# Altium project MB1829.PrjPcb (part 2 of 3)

## Sheet MCU_IO.SchDoc: MCU IOs
size A3; Date: Not used; ApprovedBy: Not used; CheckedBy: Not used; Author: Not used; CompanyName: STMicroelectronics; DrawnBy: Not used; Engineer: Not used; Organization: Not used; Address1: Not used; Address2: Not used; Address3: Not used; Address4: Not used; DocumentNumber: Not used; Revision: Not used; SheetNumber: 3; SheetTotal: 16

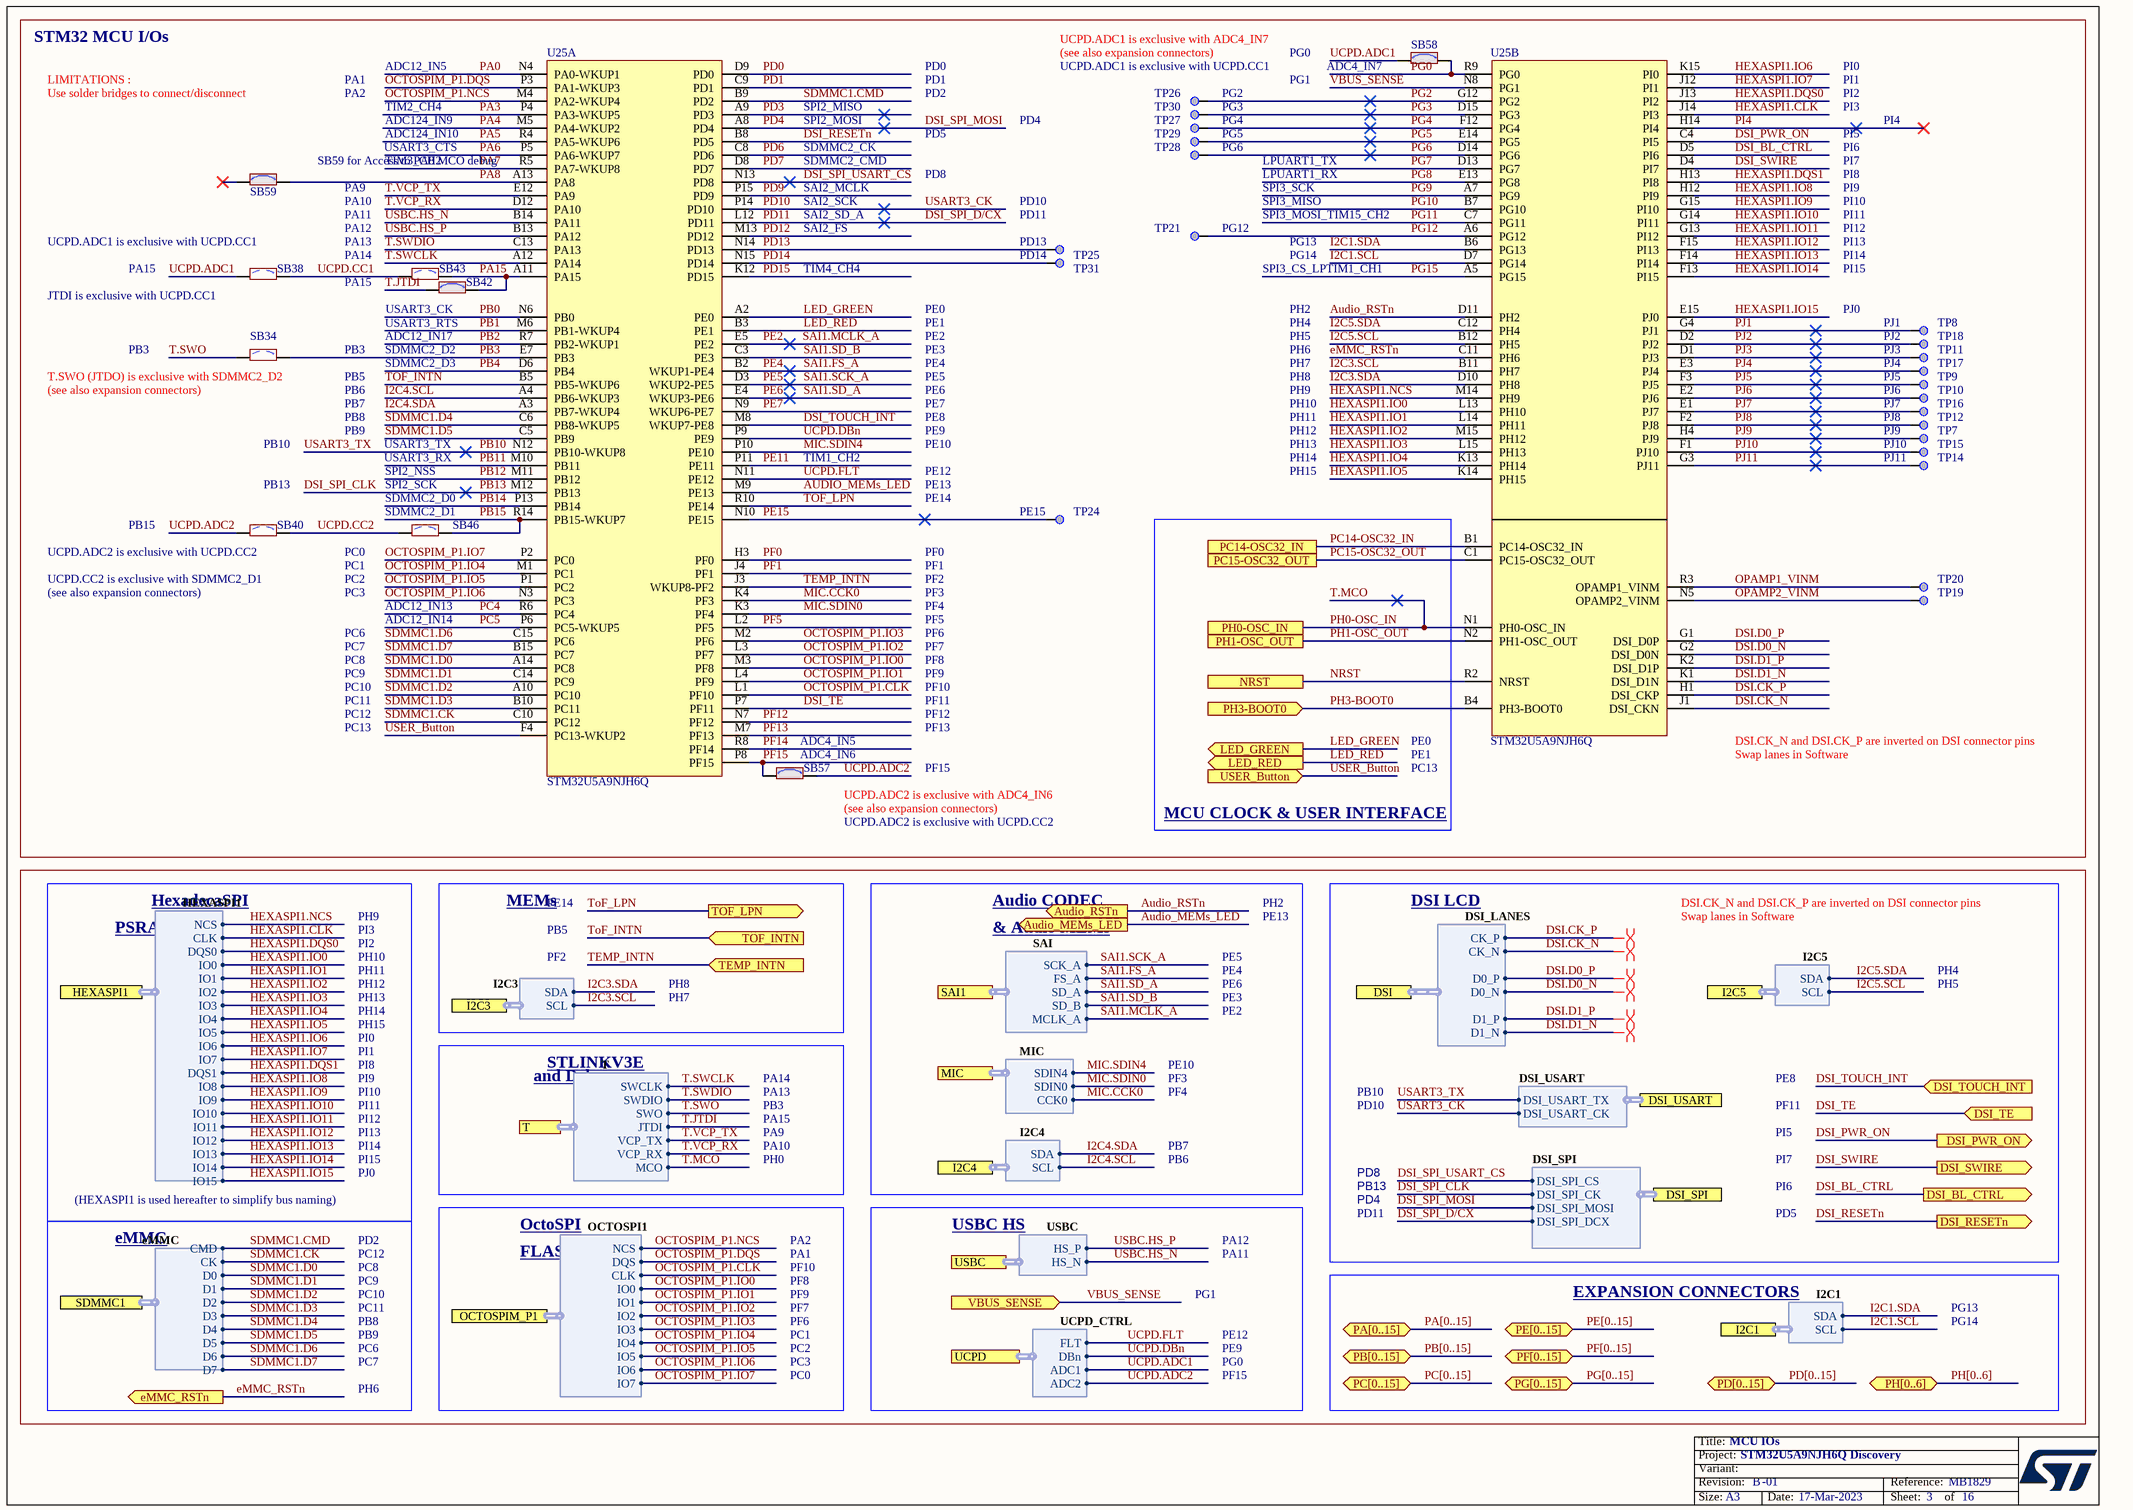
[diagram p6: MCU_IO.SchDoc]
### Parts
SB34  SB_OFF  [SOLDER-BRIDGE_R0402-0R]  (value not drawn)
SB38  SB_OFF  [SOLDER-BRIDGE_R0402-0R]  (value not drawn)
SB40  SB_OFF  [SOLDER-BRIDGE_R0402-0R]  (value not drawn)
SB42  SB_ON  [SOLDER-BRIDGE_R0402-0R]  (value not drawn)
SB43  SB_OFF  [SOLDER-BRIDGE_R0402-0R]  (value not drawn)
SB46  SB_OFF  [SOLDER-BRIDGE_R0402-0R]  (value not drawn)
SB57  SB_ON  [SOLDER-BRIDGE_R0402-0R]  (value not drawn)
SB58  SB_ON  [SOLDER-BRIDGE_R0402-0R]  (value not drawn)
SB59  SB_ON  [SOLDER-BRIDGE_R0402-0R]  (value not drawn)
TP7  Test Point  [TP_SMD_1MM]  (value not drawn)  (no BOM)
TP8  Test Point  [TP_SMD_1MM]  (value not drawn)  (no BOM)
TP9  Test Point  [TP_SMD_1MM]  (value not drawn)  (no BOM)
TP10  Test Point  [TP_SMD_1MM]  (value not drawn)  (no BOM)
TP11  Test Point  [TP_SMD_1MM]  (value not drawn)  (no BOM)
TP12  Test Point  [TP_SMD_1MM]  (value not drawn)  (no BOM)
TP14  Test Point  [TP_SMD_1MM]  (value not drawn)  (no BOM)
TP15  Test Point  [TP_SMD_1MM]  (value not drawn)  (no BOM)
TP16  Test Point  [TP_SMD_1MM]  (value not drawn)  (no BOM)
TP17  Test Point  [TP_SMD_1MM]  (value not drawn)  (no BOM)
TP18  Test Point  [TP_SMD_1MM]  (value not drawn)  (no BOM)
TP19  Test Point  [TP_SMD_1MM]  (value not drawn)  (no BOM)
TP20  Test Point  [TP_SMD_1MM]  (value not drawn)  (no BOM)
TP21  Test Point  [TP_SMD_1MM]  (value not drawn)  (no BOM)
TP24  Test Point  [TP_SMD_1MM]  (value not drawn)  (no BOM)
TP25  Test Point  [TP_SMD_1MM]  (value not drawn)  (no BOM)
TP26  Test Point  [TP_SMD_1MM]  (value not drawn)  (no BOM)
TP27  Test Point  [TP_SMD_1MM]  (value not drawn)  (no BOM)
TP28  Test Point  [TP_SMD_1MM]  (value not drawn)  (no BOM)
TP29  Test Point  [TP_SMD_1MM]  (value not drawn)  (no BOM)
TP30  Test Point  [TP_SMD_1MM]  (value not drawn)  (no BOM)
TP31  Test Point  [TP_SMD_1MM]  (value not drawn)  (no BOM)
U25  value STM32U5A9NJH6Q  [ICC_TFBGA216_13X13_P080_H1P10_CODE-A0L2]  (hidden comment: STM32U599NJH6Q_BGA216_SMPS)  (parts A,B of 3)

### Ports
Audio_MEMs_LED (out), Audio_RSTn (out), DSI (harness DSI_LANES), DSI_BL_CTRL (out), DSI_PWR_ON (out), DSI_RESETn (out), DSI_SPI (harness DSI_SPI), DSI_SWIRE (out), DSI_TE (in), DSI_TOUCH_INT (in), DSI_USART (harness DSI_USART), eMMC_RSTn (out), HEXASPI1 (harness HEXASPI1), I2C1 (harness I2C1), I2C3 (harness I2C3), I2C4 (harness I2C4), I2C5 (harness I2C5), LED_GREEN (out), LED_RED (out), MIC (harness MIC), NRST, OCTOSPIM_P1 (harness OCTOSPI1), PA[0..15] (bidir), PB[0..15] (bidir), PC14-OSC32_IN, PC15-OSC32_OUT, PC[0..15] (bidir), PD[0..15] (bidir), PE[0..15] (bidir), PF[0..15] (bidir), PG[0..15] (bidir), PH0-OSC_IN, PH1-OSC_OUT, PH3-BOOT0 (in), PH[0..6] (bidir), SAI1 (harness SAI), SDMMC1 (harness eMMC), T (harness T), TEMP_INTN (in), TOF_INTN (in), TOF_LPN (out), UCPD (harness UCPD_CTRL), USBC (harness USBC), USER_Button (in), VBUS_SENSE (in)

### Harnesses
T: SWCLK, SWDIO, SWO, JTDI, VCP_RX, VCP_TX, MCO
MIC: SDIN0, CCK0, SDIN4
OCTOSPI1: IO1, IO0, CLK, NCS, IO2, IO3, IO5, IO4, IO6, IO7, DQS
eMMC: D0, CMD, CK, D1, D2, D3, D4, D5, D6, D7
SAI: SD_B, FS_A, SD_A, SCK_A, MCLK_A
DSI_LANES: CK_P, CK_N, D0_P, D0_N, D1_N, D1_P
USBC: HS_P, HS_N
DSI_SPI: DSI_SPI_CS, DSI_SPI_MOSI, DSI_SPI_CK, DSI_SPI_DCX
DSI_USART: DSI_USART_CK, DSI_USART_TX
I2C4: SDA, SCL
I2C5: SDA, SCL
HEXASPI1: IO1, IO0, DQS0, NCS, IO2, IO3, IO5, IO4, IO6, IO7, CLK, DQS1, IO8, IO9, IO10, IO11, IO12, IO13, IO14, IO15
UCPD_CTRL: FLT, DBn, ADC1, ADC2
I2C1: SDA, SCL
I2C3: SDA, SCL

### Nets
AUDIO_MEMs_LED: U25.M9(PE13) ; port Audio_MEMs_LED
Audio_RSTn: U25.D11(PH2) ; port Audio_RSTn
DSI.CK_N: U25.J1(DSI_CKN) ; port DSI.CK_N
DSI.CK_P: U25.H1(DSI_CKP) ; port DSI.CK_P
DSI.D0_N: U25.G2(DSI_D0N) ; port DSI.D0_N
DSI.D0_P: U25.G1(DSI_D0P) ; port DSI.D0_P
DSI.D1_N: U25.K1(DSI_D1N) ; port DSI.D1_N
DSI.D1_P: U25.K2(DSI_D1P) ; port DSI.D1_P
DSI_BL_CTRL: U25.D5(PI6) ; port DSI_BL_CTRL
DSI_PWR_ON: U25.C4(PI5) ; port DSI_PWR_ON
DSI_RESETn: U25.B8(PD5) ; port DSI_RESETn
DSI_SPI_CLK: U25.M12(PB13) ; port DSI_SPI.DSI_SPI_CK  [also labelled PB13]
DSI_SPI_D/CX: U25.L12(PD11) ; port DSI_SPI.DSI_SPI_DCX  [also labelled PD11]
DSI_SPI_MOSI: U25.A8(PD4) ; port DSI_SPI.DSI_SPI_MOSI  [also labelled PD4]
DSI_SPI_USART_CS: U25.N13(PD8) ; port DSI_SPI.DSI_SPI_CS
DSI_SWIRE: U25.D4(PI7) ; port DSI_SWIRE
DSI_TE: U25.P7(PF11) ; port DSI_TE
DSI_TOUCH_INT: U25.M8(WKUP7-PE8) ; port DSI_TOUCH_INT
eMMC_RSTn: U25.C11(PH6) ; port eMMC_RSTn
HEXASPI1.CLK: U25.J14(PI3) ; port HEXASPI1.CLK
HEXASPI1.DQS0: U25.J13(PI2) ; port HEXASPI1.DQS0
HEXASPI1.DQS1: U25.H13(PI8) ; port HEXASPI1.DQS1
HEXASPI1.IO0: U25.L13(PH10) ; port HEXASPI1.IO0
HEXASPI1.IO1: U25.L14(PH11) ; port HEXASPI1.IO1
HEXASPI1.IO2: U25.M15(PH12) ; port HEXASPI1.IO2
HEXASPI1.IO3: U25.L15(PH13) ; port HEXASPI1.IO3
HEXASPI1.IO4: U25.K13(PH14) ; port HEXASPI1.IO4
HEXASPI1.IO5: U25.K14(PH15) ; port HEXASPI1.IO5
HEXASPI1.IO6: U25.K15(PI0) ; port HEXASPI1.IO6
HEXASPI1.IO7: U25.J12(PI1) ; port HEXASPI1.IO7
HEXASPI1.IO8: U25.H12(PI9) ; port HEXASPI1.IO8
HEXASPI1.IO9: U25.G15(PI10) ; port HEXASPI1.IO9
HEXASPI1.IO10: U25.G14(PI11) ; port HEXASPI1.IO10
HEXASPI1.IO11: U25.G13(PI12) ; port HEXASPI1.IO11
HEXASPI1.IO12: U25.F15(PI13) ; port HEXASPI1.IO12
HEXASPI1.IO13: U25.F14(PI14) ; port HEXASPI1.IO13
HEXASPI1.IO14: U25.F13(PI15) ; port HEXASPI1.IO14
HEXASPI1.IO15: U25.E15(PJ0) ; port HEXASPI1.IO15
HEXASPI1.NCS: U25.M14(PH9) ; port HEXASPI1.NCS
I2C1.SCL: U25.D7(PG14) ; port I2C1.SCL
I2C1.SDA: U25.B6(PG13) ; port I2C1.SDA
I2C3.SCL: U25.B11(PH7) ; port I2C3.SCL
I2C3.SDA: U25.D10(PH8) ; port I2C3.SDA
I2C4.SCL: U25.A4(PB6-WKUP3) ; port I2C4.SCL
I2C4.SDA: U25.A3(PB7-WKUP4) ; port I2C4.SDA
I2C5.SCL: U25.B12(PH5) ; port I2C5.SCL
I2C5.SDA: U25.C12(PH4) ; port I2C5.SDA
LED_GREEN: U25.A2(PE0) ; port LED_GREEN
LED_RED: U25.B3(PE1) ; port LED_RED
MIC.CCK0: U25.K4(PF3) ; port MIC.CCK0
MIC.SDIN0: U25.K3(PF4) ; port MIC.SDIN0
MIC.SDIN4: U25.P10(PE10) ; port MIC.SDIN4
NRST: U25.R2(NRST) ; port NRST
OCTOSPIM_P1.CLK: U25.L1(PF10) ; port OCTOSPIM_P1.CLK
OCTOSPIM_P1.DQS: U25.P3(PA1-WKUP3) ; port OCTOSPIM_P1.DQS
OCTOSPIM_P1.IO0: U25.M3(PF8) ; port OCTOSPIM_P1.IO0
OCTOSPIM_P1.IO1: U25.L4(PF9) ; port OCTOSPIM_P1.IO1
OCTOSPIM_P1.IO2: U25.L3(PF7) ; port OCTOSPIM_P1.IO2
OCTOSPIM_P1.IO3: U25.M2(PF6) ; port OCTOSPIM_P1.IO3
OCTOSPIM_P1.IO4: U25.M1(PC1) ; port OCTOSPIM_P1.IO4
OCTOSPIM_P1.IO5: U25.P1(PC2) ; port OCTOSPIM_P1.IO5
OCTOSPIM_P1.IO6: U25.N3(PC3) ; port OCTOSPIM_P1.IO6
OCTOSPIM_P1.IO7: U25.P2(PC0) ; port OCTOSPIM_P1.IO7
OCTOSPIM_P1.NCS: U25.M4(PA2-WKUP4) ; port OCTOSPIM_P1.NCS
OPAMP1_VINM: TP20.1 U25.R3(OPAMP1_VINM)
OPAMP2_VINM: TP19.1 U25.N5(OPAMP2_VINM)
PA0: U25.N4(PA0-WKUP1)
PA3: U25.P4(PA3-WKUP5)
PA4: U25.M5(PA4-WKUP2)
PA5: U25.R4(PA5-WKUP6)
PA6: U25.P5(PA6-WKUP7)
PA7: U25.R5(PA7-WKUP8)
PA8: SB59.2 U25.A13(PA8)
PA15: SB42.2 SB43.2 U25.A11(PA15)
PB0: U25.N6(PB0)
PB1: U25.M6(PB1-WKUP4)
PB2: U25.R7(PB2-WKUP1)
PB3: SB34.2 U25.E7(PB3)
PB4: U25.D6(PB4)
PB10: U25.N12(PB10-WKUP8) ; port DSI_USART.DSI_USART_TX  [also labelled USART3_TX]
PB11: U25.M10(PB11)
PB12: U25.M11(PB12)
PB14: U25.P13(PB14)
PB15: SB46.2 U25.R14(PB15-WKUP7)
PC4: U25.R6(PC4)
PC5: U25.P6(PC5-WKUP5)
PC14-OSC32_IN: U25.B1(PC14-OSC32_IN) ; port PC14-OSC32_IN
PC15-OSC32_OUT: U25.C1(PC15-OSC32_OUT) ; port PC15-OSC32_OUT
PD0: U25.D9(PD0)
PD1: U25.C9(PD1)
PD3: U25.A9(PD3)
PD6: U25.C8(PD6)
PD7: U25.D8(PD7)
PD9: U25.P15(PD9)
PD10: U25.P14(PD10) ; port DSI_USART.DSI_USART_CK  [also labelled USART3_CK]
PD12: U25.M13(PD12)
PD13: TP25.1 U25.N14(PD13)
PD14: TP31.1 U25.N15(PD14)
PD15: U25.K12(PD15)
PE2: U25.E5(PE2) ; port SAI1.MCLK_A  [also labelled SAI1.MCLK_A]
PE4: U25.B2(WKUP1-PE4) ; port SAI1.FS_A  [also labelled SAI1.FS_A]
PE5: U25.D3(WKUP2-PE5) ; port SAI1.SCK_A  [also labelled SAI1.SCK_A]
PE6: U25.E4(WKUP3-PE6) ; port SAI1.SD_A  [also labelled SAI1.SD_A]
PE7: U25.N9(WKUP6-PE7)
PE11: U25.P11(PE11)
PE15: TP24.1 U25.N10(PE15)
PF0: U25.H3(PF0)
PF1: U25.J4(PF1)
PF5: U25.L2(PF5)
PF12: U25.N7(PF12)
PF13: U25.M7(PF13)
PF14: U25.R8(PF14)
PF15: SB57.1 U25.P8(PF15)
PG0: SB58.2 U25.R9(PG0)
PG2: TP26.1 U25.G12(PG2)
PG3: TP30.1 U25.D15(PG3)
PG4: TP27.1 U25.F12(PG4)
PG5: TP29.1 U25.E14(PG5)
PG6: TP28.1 U25.D14(PG6)
PG7: U25.D13(PG7)
PG8: U25.E13(PG8)
PG9: U25.A7(PG9)
PG10: U25.B7(PG10)
PG11: U25.C7(PG11)
PG12: TP21.1 U25.A6(PG12)
PG15: U25.A5(PG15)
PH0-OSC_IN: U25.N1(PH0-OSC_IN) ; port PH0-OSC_IN, port T.MCO  [also labelled T.MCO]
PH1-OSC_OUT: U25.N2(PH1-OSC_OUT) ; port PH1-OSC_OUT
PH3-BOOT0: U25.B4(PH3-BOOT0) ; port PH3-BOOT0
PI4: U25.H14(PI4)
PJ1: TP8.1 U25.G4(PJ1)
PJ2: TP18.1 U25.D2(PJ2)
PJ3: TP11.1 U25.D1(PJ3)
PJ4: TP17.1 U25.E3(PJ4)
PJ5: TP9.1 U25.F3(PJ5)
PJ6: TP10.1 U25.E2(PJ6)
PJ7: TP16.1 U25.E1(PJ7)
PJ8: TP12.1 U25.F2(PJ8)
PJ9: TP7.1 U25.H4(PJ9)
PJ10: TP15.1 U25.F1(PJ10)
PJ11: TP14.1 U25.G3(PJ11)
SAI1.SD_B: U25.C3(PE3) ; port SAI1.SD_B
SDMMC1.CK: U25.C10(PC12) ; port SDMMC1.CK
SDMMC1.CMD: U25.B9(PD2) ; port SDMMC1.CMD
SDMMC1.D0: U25.A14(PC8) ; port SDMMC1.D0
SDMMC1.D1: U25.C14(PC9) ; port SDMMC1.D1
SDMMC1.D2: U25.A10(PC10) ; port SDMMC1.D2
SDMMC1.D3: U25.B10(PC11) ; port SDMMC1.D3
SDMMC1.D4: U25.C6(PB8-WKUP5) ; port SDMMC1.D4
SDMMC1.D5: U25.C5(PB9) ; port SDMMC1.D5
SDMMC1.D6: U25.C15(PC6) ; port SDMMC1.D6
SDMMC1.D7: U25.B15(PC7) ; port SDMMC1.D7
T.JTDI: SB42.1 ; port T.JTDI
T.SWCLK: U25.A12(PA14) ; port T.SWCLK
T.SWDIO: U25.C13(PA13) ; port T.SWDIO
T.SWO: SB34.1 ; port T.SWO
T.VCP_RX: U25.D12(PA10) ; port T.VCP_RX
T.VCP_TX: U25.E12(PA9) ; port T.VCP_TX
TEMP_INTN: U25.J3(WKUP8-PF2) ; port TEMP_INTN
ToF_INTN: U25.B5(PB5-WKUP6) ; port TOF_INTN
ToF_LPN: U25.R10(PE14) ; port TOF_LPN
UCPD.ADC1: SB38.1 SB58.1 ; port UCPD.ADC1
UCPD.ADC2: SB40.1 SB57.2 ; port UCPD.ADC2
UCPD.CC1: SB38.2 SB43.1
UCPD.CC2: SB40.2 SB46.1
UCPD.DBn: U25.P9(PE9) ; port UCPD.DBn
UCPD.FLT: U25.N11(PE12) ; port UCPD.FLT
USBC.HS_N: U25.B14(PA11) ; port USBC.HS_N
USBC.HS_P: U25.B13(PA12) ; port USBC.HS_P
USER_Button: U25.F4(PC13-WKUP2) ; port USER_Button
VBUS_SENSE: U25.N8(PG1) ; port VBUS_SENSE

Not connected (* = marked no-connect by the designer): SB59 1*

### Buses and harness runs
bus PA[0..15] = port PA[0..15]
bus PB[0..15] = port PB[0..15]
bus PC[0..15] = port PC[0..15]
bus PD[0..15] = port PD[0..15]
bus PE[0..15] = port PE[0..15]
bus PF[0..15] = port PF[0..15]
bus PG[0..15] = port PG[0..15]
bus PH[0..6] = port PH[0..6]

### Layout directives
differential pair; rule Impedance Constraint [Min = 95.00    Max = 105.0    ]: DSI.CK_N, DSI.CK_P, DSI.D0_N, DSI.D0_P, DSI.D1_N, DSI.D1_P

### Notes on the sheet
- STM32 MCU I/Os
- UCPD.ADC1 is exclusive with ADC4_IN7
- Use solder bridges to connect/disconnect
- LIMITATIONS :
- PA1
- PA2
- TIM2_CH4
- ADC12_IN5
- SPI2_MISO
- PD2
- PD1
- PD0
- UCPD.ADC1 is exclusive with UCPD.CC1
- (see also expansion connectors)
- PG2
- PG3
- PG1
- PG0
- (near SB58) ADC4_IN7
- PI0
- PI1
- PI2
- PI3
- (near SB59) SB59 for Access to PA8 MCO debug
- ADC124_IN9
- ADC124_IN10
- TIM3_CH2
- USART3_CTS
- SDMMC2_CK
- SDMMC2_CMD
- SPI2_MOSI
- PD8
- PD5
- PD4
- PG4
- PG5
- PG6
- LPUART1_TX
- LPUART1_RX
- PI8
- PI6
- PI7
- PI5
- PI4
- (near SB38) UCPD.ADC1 is exclusive with UCPD.CC1
- PA13
- PA10
- PA9
- PA12
- PA11
- SAI2_MCLK
- SAI2_SCK
- SAI2_SD_A
- SAI2_FS
- PD10
- PD11
- PD13
- (near TP21) PG12
- SPI3_SCK
- SPI3_MISO
- SPI3_MOSI_TIM15_CH2
- PG13
- PI9
- PI10
- PI11
- PI12
- PI13
- (near SB38) JTDI is exclusive with UCPD.CC1
- PA15
- PA14
- (near SB42) USART3_CK
- TIM4_CH4
- PE0
- PD14
- SPI3_CS_LPTIM1_CH1
- PG14
- PH2
- PI14
- PI15
- PJ0
- (near SB34) T.SWO (JTDO) is exclusive with SDMMC2_D2
- PB3
- PB5
- SDMMC2_D2
- SDMMC2_D3
- ADC12_IN17
- USART3_RTS
- PE1
- PE2
- PE3
- PE4
- PE5
- PH4
- PH5
- PH6
- PH7
- PH8
- PJ1
- PJ2
- PJ3
- PJ4
- PJ5
- (near SB34) (see also expansion connectors)
- PB10
- PB8
- PB9
- PB6
- PB7
- USART3_TX
- PE6
- PE7
- PE8
- PE10
- PE9
- PH9
- PH11
- PH12
- PH13
- PH10
- PJ6
- PJ7
- PJ8
- PJ9
- PJ10
- (near SB40) PB13
- (near SB46) SDMMC2_D0
- (near SB46) SDMMC2_D1
- (near SB46) SPI2_SCK
- SPI2_NSS
- USART3_RX
- TIM1_CH2
- PE13
- PE14
- PE12
- (near TP24) PE15
- PH14
- PH15
- PJ11
- (near SB40) UCPD.CC2 is exclusive with SDMMC2_D1
- (near SB40) UCPD.ADC2 is exclusive with UCPD.CC2
- PB15
- PC0
- PC1
- PC2
- PF1
- PF0
- PF2
- PC6
- PC7
- PC3
- ADC12_IN14
- ADC12_IN13
- PF6
- PF7
- PF4
- PF3
- PF5
- PC9
- PC12
- PC8
- PC10
- PC11
- PF9
- PF8
- PF10
- PF12
- PF11
- PC13
- (near SB57) ADC4_IN5
- (near SB57) ADC4_IN6
- PF13
- PF15
- DSI.CK_N and DSI.CK_P are inverted on DSI connector pins
- Swap lanes in Software
- (near SB57) UCPD.ADC2 is exclusive with ADC4_IN6
- UCPD.ADC2 is exclusive with UCPD.CC2
- (near SB57) (see also expansion connectors)
- MCU CLOCK & USER INTERFACE
- HexadecaSPI
- MEMs
- Audio CODEC
- DSI LCD
- PSRAM
- & Audio MEMs
- and Debug
- STLINKV3E
- PH0
- PB13
- (HEXASPI1 is used hereafter to simplify bus naming)
- eMMC
- OctoSPI
- FLASH
- USBC HS
- EXPANSION CONNECTORS

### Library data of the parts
SB34 SB38 SB40 SB43 SB46 = MCD-02162: Solder Bridge 0402 OFF; Part_Type: Misc; Manufacturer_Part_Number: RC0402JR-070RL; Manufacturer: YAGEO; Part_Preference: Recommended; Order_Code_RS: 618-5804; Component_Country_Of_Origin: China
SB42 SB57-SB59 = MCD-01618: Solder Bridge 0402 ON; Part_Type: Misc; Manufacturer_Part_Number: RC0402JR-070RL; Manufacturer: YAGEO; Part_Preference: Recommended; Order_Code_RS: 618-5804; Component_Country_Of_Origin: China
TP7-TP12 TP14-TP21 TP24-TP31 = MCD-00074: Test Point 1mm; Part_Type: Misc; Part_Preference: Recommended
U25 = MCD-03270: MCU, ARM Cortex-M33, 4MB Flash, 2.5MB RAM, With Crypto; Part_Type: IC; Part_Preference: Recommended; Manufacturer: STMICROELECTRONICS; Component_Country_Of_Origin: Unknown; ShowFields: YES; ID: 5386

## Sheet MCU_PWR.SchDoc: MCU PWR
size A4; Date: Not used; ApprovedBy: Not used; CheckedBy: Not used; Author: Not used; CompanyName: STMicroelectronics; DrawnBy: Not used; Engineer: Not used; Organization: Not used; Address1: Not used; Address2: Not used; Address3: Not used; Address4: Not used; DocumentNumber: Not used; Revision: Not used; SheetNumber: 5; SheetTotal: 16

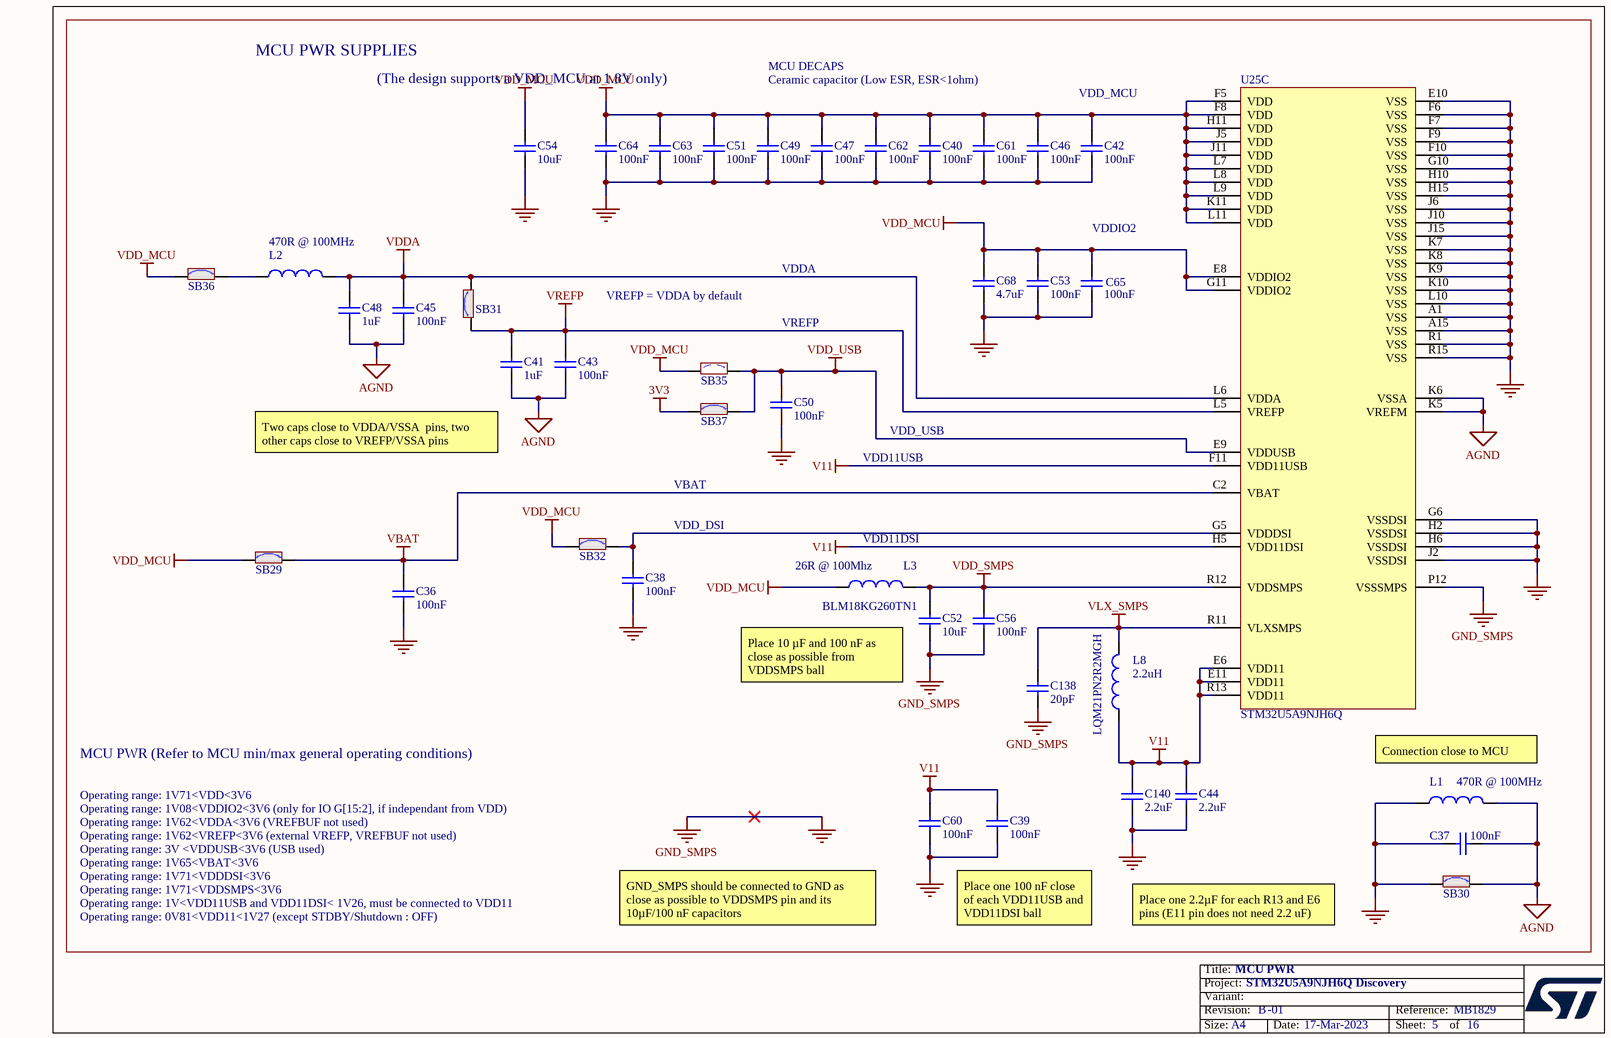
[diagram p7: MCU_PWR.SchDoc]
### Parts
C36  value 100nF  [C0402]  (hidden comment: Capacitor)
C37  value 100nF  [C0402]  (hidden comment: Capacitor)
C38  value 100nF  [C0402]  (hidden comment: Capacitor)
C39  value 100nF  [C0402]  (hidden comment: Capacitor)
C40  value 100nF  [C0402]  (hidden comment: Capacitor)
C41  value 1uF  [C0402]  (hidden comment: Capacitor)
C42  value 100nF  [C0402]  (hidden comment: Capacitor)
C43  value 100nF  [C0402]  (hidden comment: Capacitor)
C44  value 2.2uF  [C0402]  (hidden comment: Capacitor)
C45  value 100nF  [C0402]  (hidden comment: Capacitor)
C46  value 100nF  [C0402]  (hidden comment: Capacitor)
C47  value 100nF  [C0402]  (hidden comment: Capacitor)
C48  value 1uF  [C0402]  (hidden comment: Capacitor)
C49  value 100nF  [C0402]  (hidden comment: Capacitor)
C50  value 100nF  [C0402]  (hidden comment: Capacitor)
C51  value 100nF  [C0402]  (hidden comment: Capacitor)
C52  value 10uF  [C0603_H0P8]  (hidden comment: Capacitor)
C53  value 100nF  [C0402]  (hidden comment: Capacitor)
C54  value 10uF  [C0402]  (hidden comment: Capacitor)
C56  value 100nF  [C0402]  (hidden comment: Capacitor)
C60  value 100nF  [C0402]  (hidden comment: Capacitor)
C61  value 100nF  [C0402]  (hidden comment: Capacitor)
C62  value 100nF  [C0402]  (hidden comment: Capacitor)
C63  value 100nF  [C0402]  (hidden comment: Capacitor)
C64  value 100nF  [C0402]  (hidden comment: Capacitor)
C65  value 100nF  [C0402]  (hidden comment: Capacitor)
C68  value 4.7uF  [C0402]  (hidden comment: Capacitor)
C138  value 20pF  [C0402]  (hidden comment: Capacitor)
C140  value 2.2uF  [C0402]  (hidden comment: Capacitor)
L1  value 470R @ 100MHz  [IND_0402_MURATA_BLM15H_H0P5]  (hidden comment: Inductor)
L2  value 470R @ 100MHz  [IND_0402_MURATA_BLM15H_H0P5]  (hidden comment: Inductor)
L3  value 26R @ 100Mhz  Manufacturer_Part_Number: BLM18KG260TN1  [FIL_0603_H0P65]  (hidden comment: BEAD)
L8  value 2.2uH  Manufacturer_Part_Number: LQM21PN2R2MGH  [L0805_H0P9]  (hidden comment: Inductor)
SB29  SB_ON  [SOLDER-BRIDGE_R0402-0R]  (value not drawn)
SB30  SB_ON  [SOLDER-BRIDGE_R0402-0R]  (value not drawn)
SB31  SB_ON  [SOLDER-BRIDGE_R0402-0R]  (value not drawn)
SB32  SB_ON  [SOLDER-BRIDGE_R0402-0R]  (value not drawn)
SB35  SB_OFF  [SOLDER-BRIDGE_R0402-0R]  (value not drawn)
SB36  SB_ON  [SOLDER-BRIDGE_R0402-0R]  (value not drawn)
SB37  SB_ON  [SOLDER-BRIDGE_R0402-0R]  (value not drawn)
U25  value STM32U5A9NJH6Q  [ICC_TFBGA216_13X13_P080_H1P10_CODE-A0L2]  (hidden comment: STM32U599NJH6Q_BGA216_SMPS)  (part C of 3)

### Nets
3V3: SB37.1
AGND: C37.2 C41.1 C43.1 C45.1 C48.1 L1.2 SB30.2 U25.K5(VREFM) U25.K6(VSSA)
GND: C36.1 C37.1 C38.1 C39.1 C40.1 C42.1 C44.1 C46.1 C47.1 C49.1 C50.1 C51.1 C52.1 C53.1 C54.1 C56.1 C60.1 C61.1 C62.1 C63.1 C64.1 C65.1 C68.1 C138.1 C140.1 L1.1 SB30.1 U25.A1(VSS) U25.A15(VSS) U25.E10(VSS) U25.F6(VSS) U25.F7(VSS) U25.F9(VSS) U25.F10(VSS) U25.G6(VSSDSI) U25.G10(VSS) U25.H2(VSSDSI) U25.H6(VSSDSI) U25.H10(VSS) U25.H15(VSS) U25.J2(VSSDSI) U25.J6(VSS) U25.J10(VSS) U25.J15(VSS) U25.K7(VSS) U25.K8(VSS) U25.K9(VSS) U25.K10(VSS) U25.L10(VSS) U25.P12(VSSSMPS) U25.R1(VSS) U25.R15(VSS)  [also labelled GND_SMPS]
V11: C39.2 C44.2 C60.2 C140.2 L8.1 U25.E6(VDD11) U25.E11(VDD11) U25.F11(VDD11USB) U25.H5(VDD11DSI) U25.R13(VDD11)
VBAT: C36.2 SB29.2 U25.C2(VBAT)
VDD_MCU: C40.2 C42.2 C46.2 C47.2 C49.2 C51.2 C53.2 C54.2 C61.2 C62.2 C63.2 C64.2 C65.2 C68.2 L3.1 SB29.1 SB32.1 SB35.1 SB36.1 U25.E8(VDDIO2) U25.F5(VDD) U25.F8(VDD) U25.G11(VDDIO2) U25.H11(VDD) U25.J5(VDD) U25.J11(VDD) U25.K11(VDD) U25.L7(VDD) U25.L8(VDD) U25.L9(VDD) U25.L11(VDD)
VDD_SMPS: C52.2 C56.2 L3.2 U25.R12(VDDSMPS)
VDD_USB: C50.2 SB35.2 SB37.2 U25.E9(VDDUSB)
VDDA: C45.2 C48.2 L2.2 SB31.2 U25.L6(VDDA)
VLX_SMPS: C138.2 L8.2 U25.R11(VLXSMPS)
VREFP: C41.2 C43.2 SB31.1 U25.L5(VREFP)
NetC38_2: C38.2 SB32.2 U25.G5(VDDDSI)
NetL2_1: L2.1 SB36.2

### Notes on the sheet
- MCU PWR SUPPLIES
- (The design supports a VDD_MCU at 1.8V only)
- MCU DECAPS
- Ceramic capacitor (Low ESR, ESR<1ohm)
- VDD_MCU
- (near C65) VDDIO2
- VREFP = VDDA by default
- VDDA
- VREFP
- (near C41) Two caps close to VDDA/VSSA  pins, two other caps close to VREFP/VSSA pins
- VDD_USB
- VBAT
- VDD11USB
- VDD_DSI
- (near L3) VDD11DSI
- Place 10 µF and 100 nF as close as possible from VDDSMPS ball
- MCU PWR (Refer to MCU min/max general operating conditions)
- Connection close to MCU
- Operating range: 1V71<VDD<3V6
- Operating range: 1V08<VDDIO2<3V6 (only for IO G[15:2], if independant from VDD)
- Operating range: 1V62<VDDA<3V6 (VREFBUF not used)
- Operating range: 3V <VDDUSB<3V6 (USB used)
- Operating range: 1V62<VREFP<3V6 (external VREFP, VREFBUF not used)
- Operating range: 1V65<VBAT<3V6
- Operating range: 1V71<VDDSMPS<3V6
- Operating range: 1V71<VDDDSI<3V6
- Operating range: 1V<VDD11USB and VDD11DSI< 1V26, must be connected to VDD11
- Operating range: 0V81<VDD11<1V27 (except STDBY/Shutdown : OFF)
- GND_SMPS should be connected to GND as close as possible to VDDSMPS pin and its 10µF/100 nF capacitors
- Place one 100 nF close of each VDD11USB and VDD11DSI ball
- Place one 2.2µF for each R13 and E6 pins (E11 pin does not need 2.2 uF)

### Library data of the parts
C36-C40 C42 C43 C45-C47 C49-C51 C53 C56 C60-C65 = MCD-00006: Capacitor, MLCC, 100nF, 16V, X7R, +/-10%, 0402, T=0.5mm; Manufacturer_Part_Number: CC0402KRX7R7BB104; Manufacturer: YAGEO; Part_Preference: Recommended; Order_Code_RS: 616-9701; Component_Country_Of_Origin: China
C41 C48 = MCD-01722: Capacitor, MLCC, 1uF, 10V, X5R, +/-10%, 0402, T=0.5mm; Manufacturer_Part_Number: CC0402KRX5R6BB105; Manufacturer: YAGEO; Part_Preference: Recommended; Component_Country_Of_Origin: China
C44 C140 = MCD-02606: Capacitor, MLCC, 2.2uF, 6.3V, X5R, +/-10%, 0402, T=0.5mm; Part_Preference: Recommended; Manufacturer: YAGEO; Manufacturer_Part_Number: CC0402KRX5R5BB225; Order_Code_RS: 1992205
C52 = MCD-02605: Capacitor, MLCC, 10uF, 10V, X5R, +/-10%, 0603, T=0.8mm; Part_Preference: Recommended; Manufacturer: YAGEO; Manufacturer_Part_Number: CC0603KRX5R6BB106; Order_Code_RS: 2006536
C54 = MCD-01716: Capacitor, MLCC, 10uF, 6V3, X5R, +/-20%, 0402, T=0.5mm; Part_Preference: Recommended; Manufacturer: YAGEO; Manufacturer_Part_Number: CC0402MRX5R5BB106; Component_Country_Of_Origin: China
C68 = MCD-02608: Capacitor, MLCC, 4.7uF, 6.3V, X5R, +/-10%, 0402, T=0.5mm; Part_Preference: Recommended; Manufacturer: YAGEO; Manufacturer_Part_Number: CC0402KRX5R5BB475
C138 = MCD-00016: Capacitor, MLCC, 20pF, 50V, NPO, +/- 5%, 0402, T=0.5mm; Manufacturer: YAGEO; Manufacturer_Part_Number: CC0402JRNPO9BN200; Part_Preference: Recommended; Component_Country_Of_Origin: China
L1 L2 = MCD-01986: Ferrite bead, 470R @ 100MHz, +/-25%, 200mA, 0R6, 0402, T=0.55mm; Manufacturer_Part_Number: BLM15BD471SN1D; Manufacturer: MURATA; Part_Preference: Recommended; Order_Code_RS: 166-9836; Component_Country_Of_Origin: Japan
L3 = MCD-00305: Ferrite bead, 26R @ 100Mhz, +/-25%, 6000mA, 0R007, 0603, T=0.75mm; Part_Type: Inductor; Manufacturer: MURATA; Part_Preference: Recommended; Order_Code_RS: 747-4723; Component_Country_Of_Origin: Japan
L8 = MCD-01060: Inductor, 2.2uH, +/-20%, 0.7A, 0R156, 0805, T=0.9mm; Manufacturer: MURATA; Part_Preference: Recommended; Order_Code_RS: 166-9883; Component_Country_Of_Origin: Japan
SB29-SB32 SB36 SB37 = MCD-01618: as SB42 on sheet MCU_IO
SB35 = MCD-02162: as SB34 on sheet MCU_IO
U25 = MCD-03270: as U25 on sheet MCU_IO

## Sheet MECHANICAL.SchDoc: MECHANICAL
size A4; Date: Not used; ApprovedBy: Not used; CheckedBy: Not used; Author: Not used; CompanyName: STMicroelectronics; DrawnBy: Not used; Engineer: Not used; Organization: Not used; Address1: Not used; Address2: Not used; Address3: Not used; Address4: Not used; DocumentNumber: Not used; Revision: Not used; SheetNumber: 16; SheetTotal: 16

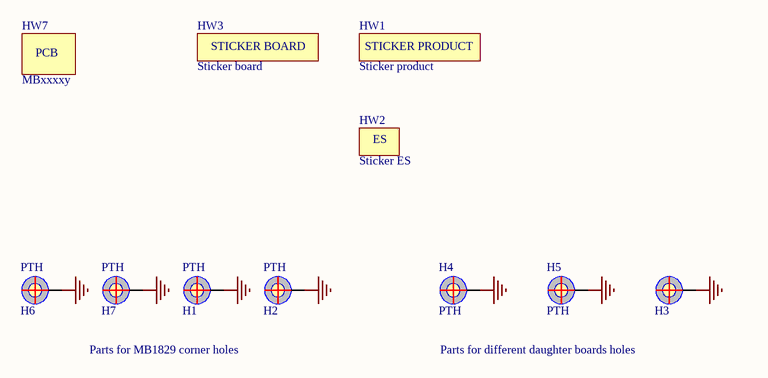
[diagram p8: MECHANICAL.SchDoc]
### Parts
H1  value PTH  [PTH_350_700_H-12]  (hidden comment: POSITION HOLE)  (no BOM)
H2  value PTH  [PTH_350_700_H-12]  (hidden comment: POSITION HOLE)  (no BOM)
H3  POSITION HOLE  [PTH_450_900]  (value not drawn)  (no BOM)
H4  value PTH  [PTH_350_500]  (hidden comment: POSITION HOLE)  (no BOM)
H5  value PTH  [PTH_350_500]  (hidden comment: POSITION HOLE)  (no BOM)
H6  value PTH  [PTH_350_700_H-12]  (hidden comment: POSITION HOLE)  (no BOM)
H7  value PTH  [PTH_350_700_H-12]  (hidden comment: POSITION HOLE)  (no BOM)
HW1  value Sticker product  [STICKER_PRODUCT_25X5]  (hidden comment: STICKER_PRODUCT)  (no BOM)
HW2  value Sticker ES  [STICKER_ES_6X6]  (hidden comment: STICKER_ES)  (no BOM)
HW3  value Sticker board  [STICKER_BOARD_25X9]  (hidden comment: STICKER_BOARD)  (no BOM)
HW7  value MBxxxxy  (hidden comment: PCB)  (no BOM)

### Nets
GND: H1.1 H2.1 H3.1 H4.1 H5.1 H6.1 H7.1

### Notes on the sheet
- Parts for MB1829 corner holes
- Parts for different daughter boards holes

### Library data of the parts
H1 H2 H6 H7 = MCD-02916: Position hole,  C7D3R5 with 12mm M3 pillar on bottom; Part_Type: Misc; Part_Preference: Recommended; ShowFields: YES; ID: 5032
H3 = MCD-01612: POSITION HOLE C9D4R5; Part_Type: Misc; Part_Preference: Recommended; ShowFields: YES; ID: 3712
H4 H5 = MCD-02915: Position Hole C5D3R5: with no pillar in 3D, with pad design = c500h350m510.; Part_Type: Misc; Part_Preference: Recommended; ShowFields: YES; ID: 5031
HW1 = MCD-02189: Sticker product 25x5 mm; Part_Preference: Recommended; Part_Type: Misc
HW2 = MCD-00234: Sticker ES 6x6 mm; Part_Type: Misc; Part_Preference: Recommended
HW3 = MCD-00235: Sticker Board 25x9 mm; Part_Preference: Recommended; Part_Type: Misc
HW7 = MCD-00216: PCB, xxxx for PCB number, Y for PCB revision; Part_Type: Misc; Part_Preference: Forbidden; ShowFields: YES; ID: 2653

## Sheet OCTOSPI_FLASH.SchDoc: OCTOSPI FLASH
size A4; Date: Not used; ApprovedBy: Not used; CheckedBy: Not used; Author: Not used; CompanyName: STMicroelectronics; DrawnBy: Not used; Engineer: Not used; Organization: Not used; Address1: Not used; Address2: Not used; Address3: Not used; Address4: Not used; DocumentNumber: Not used; Revision: Not used; SheetNumber: 6; SheetTotal: 16

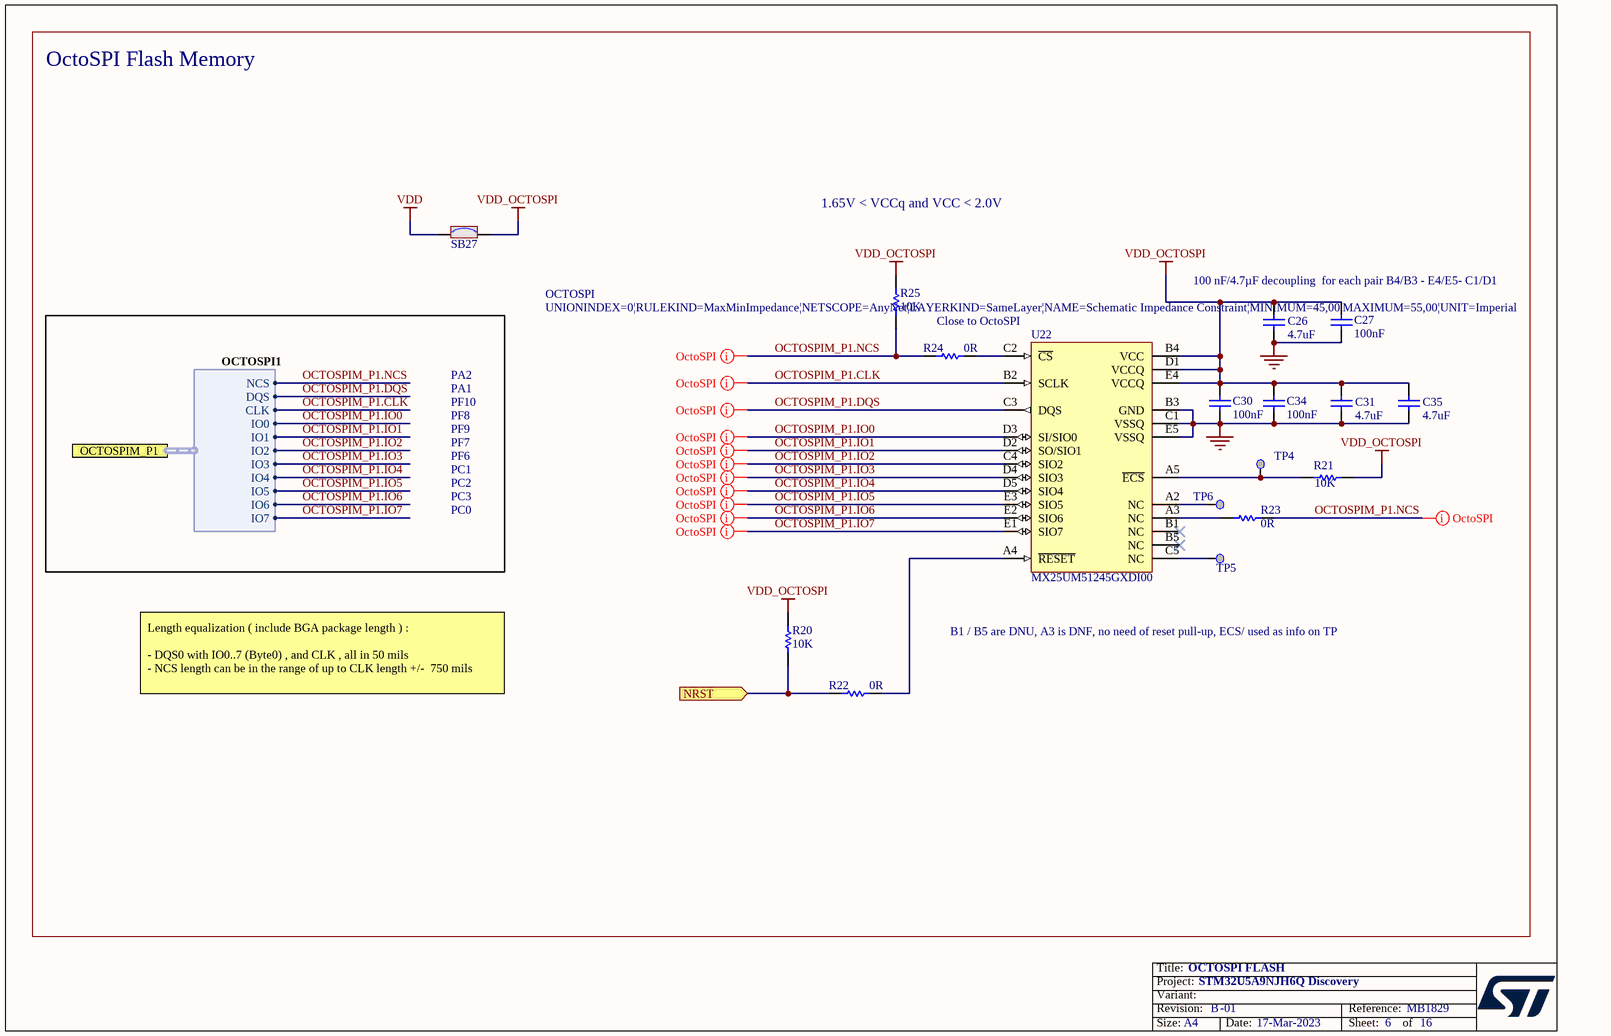
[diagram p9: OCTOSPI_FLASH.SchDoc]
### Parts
C26  value 4.7uF  [C0603]  (hidden comment: Capacitor)
C27  value 100nF  [C0402]  (hidden comment: Capacitor)
C30  value 100nF  [C0402]  (hidden comment: Capacitor)
C31  value 4.7uF  [C0603]  (hidden comment: Capacitor)
C34  value 100nF  [C0402]  (hidden comment: Capacitor)
C35  value 4.7uF  [C0603]  (hidden comment: Capacitor)
R20  value 10K  [R0402]  (hidden comment: Resistor)
R21  value 10K  [R0402]  (hidden comment: Resistor)
R22  value 0R  [R0402]  (hidden comment: Resistor)
R23  value 0R  [R0402]  (hidden comment: Resistor)
R24  value 0R  [R0402]  (hidden comment: Resistor)
R25  value 10K  [R0402]  (hidden comment: Resistor)
SB27  SB_ON  [SOLDER-BRIDGE_R0402-0R]  (value not drawn)
TP4  Test Point  [TP_SMD_1MM]  (value not drawn)  (no BOM)
TP5  Test Point  [TP_SMD_1MM]  (value not drawn)  (no BOM)
TP6  Test Point  [TP_SMD_1MM]  (value not drawn)  (no BOM)
U22  value MX25UM51245GXDI00  [ICC_BGA24_5X5-BALL-ARRAY_6X8_P1]  (hidden comment: MX25xx51245GXDx00)

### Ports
NRST (in), OCTOSPIM_P1 (harness OCTOSPI1)

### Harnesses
OCTOSPI1: IO1, IO0, CLK, NCS, IO2, IO3, IO5, IO4, IO6, IO7, DQS

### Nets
GND: C26.1 C27.1 C30.1 C31.1 C34.1 C35.1 U22.B3(GND) U22.C1(VSSQ) U22.E5(VSSQ)
VDD: SB27.1
VDD_OCTOSPI: C26.2 C27.2 C30.2 C31.2 C34.2 C35.2 R20.2 R21.2 R25.2 SB27.2 U22.B4(VCC) U22.D1(VCCQ) U22.E4(VCCQ)
NRST: R20.1 R22.1 ; port NRST
OCTOSPIM_P1.CLK: U22.B2(SCLK) ; port OCTOSPIM_P1.CLK
OCTOSPIM_P1.DQS: U22.C3(DQS) ; port OCTOSPIM_P1.DQS
OCTOSPIM_P1.IO0: U22.D3(SI/SIO0) ; port OCTOSPIM_P1.IO0
OCTOSPIM_P1.IO1: U22.D2(SO/SIO1) ; port OCTOSPIM_P1.IO1
OCTOSPIM_P1.IO2: U22.C4(SIO2) ; port OCTOSPIM_P1.IO2
OCTOSPIM_P1.IO3: U22.D4(SIO3) ; port OCTOSPIM_P1.IO3
OCTOSPIM_P1.IO4: U22.D5(SIO4) ; port OCTOSPIM_P1.IO4
OCTOSPIM_P1.IO5: U22.E3(SIO5) ; port OCTOSPIM_P1.IO5
OCTOSPIM_P1.IO6: U22.E2(SIO6) ; port OCTOSPIM_P1.IO6
OCTOSPIM_P1.IO7: U22.E1(SIO7) ; port OCTOSPIM_P1.IO7
OCTOSPIM_P1.NCS: R23.2 R24.1 R25.1 ; port OCTOSPIM_P1.NCS
NetR21_1: R21.1 TP4.1 U22.A5(~{ECS})
NetR22_2: R22.2 U22.A4(~{RESET})
NetR23_1: R23.1 U22.A3(NC)
NetR24_2: R24.2 U22.C2(~{CS})
NetTP5_1: TP5.1 U22.C5(NC)
NetTP6_1: TP6.1 U22.A2(NC)

Not connected (* = marked no-connect by the designer): U22 B1(NC)* B5(NC)*

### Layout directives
rule Matched Net Lengths [Tolerance = 1000mil]; net class OCTOSPI; rule Impedance Constraint [Min = 45.00    Max = 55.00    ]; rule Routing Layers [TopLayer - Enabled BottomLayer - Disabled]: OCTOSPIM_P1.NCS
rule Matched Net Lengths [Tolerance = 10mil]; net class OCTOSPI; rule Impedance Constraint [Min = 45.00    Max = 55.00    ]; rule Routing Layers [TopLayer - Enabled BottomLayer - Disabled]: OCTOSPIM_P1.CLK
rule Matched Net Lengths [Tolerance = 20mil]; net class OCTOSPI; rule Impedance Constraint [Min = 45.00    Max = 55.00    ]; rule Routing Layers [TopLayer - Enabled BottomLayer - Disabled]: OCTOSPIM_P1.DQS, OCTOSPIM_P1.IO0, OCTOSPIM_P1.IO1, OCTOSPIM_P1.IO2, OCTOSPIM_P1.IO3, OCTOSPIM_P1.IO4, OCTOSPIM_P1.IO5, OCTOSPIM_P1.IO6, OCTOSPIM_P1.IO7
rule Matched Net Lengths [Tolerance = 500mil]; net class OCTOSPI; rule Impedance Constraint [Min = 45.00    Max = 55.00    ]; rule Routing Layers [TopLayer - Enabled BottomLayer - Disabled]: OCTOSPIM_P1.NCS

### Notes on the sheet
- OctoSPI Flash Memory
- 1.65V < VCCq and VCC < 2.0V
- 100 nF/4.7µF decoupling  for each pair B4/B3 - E4/E5- C1/D1
- PA2
- Close to OctoSPI
- PF7
- PF9
- PF8
- PF10
- PA1
- PC0
- PC1
- PC3
- PC2
- PF6
- B1 / B5 are DNU, A3 is DNF, no need of reset pull-up, ECS/ used as info on TP
- Length equalization ( include BGA package length ) :
  - DQS0 with IO0..7 (Byte0) , and CLK , all in 50 mils
  - NCS length can be in the range of up to CLK length +/-  750 mils

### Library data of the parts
C26 C31 C35 = MCD-00009: Capacitor, MLCC, 4.7uF, 16V, X5R, +/-10%, 0603, T=0.8mm; Manufacturer_Part_Number: CC0603KRX5R7BB475; Manufacturer: YAGEO; Part_Preference: Recommended; Component_Country_Of_Origin: China
C27 C30 C34 = MCD-00006: as C36-C40 on sheet MCU_PWR
R20 R21 R25 = MCD-00053: Resistor, 10K, 0402, +/-1%, 1/16W; Manufacturer_Part_Number: RC0402FR-0710KL; Manufacturer: YAGEO; BMS_Part_Number: 9131590; Part_Preference: Recommended; Component_Country_Of_Origin: China
R22-R24 = MCD-00052: Resistor, 0R, 0402, +/-5%, 1/16W; Manufacturer_Part_Number: RC0402JR-070RL; Manufacturer: YAGEO; Part_Preference: Recommended; Order_Code_RS: 618-5804; Component_Country_Of_Origin: China
SB27 = MCD-01618: as SB42 on sheet MCU_IO
TP4-TP6 = MCD-00074: as TP7-TP12 on sheet MCU_IO
U22 = MCD-02166: Memory,Octo-SPI-NOR,512Mb,x1/x8,133/200MHz,1.8V,DTR,BGA24, CMOS MXSMIO; Part_Type: IC; Manufacturer: MACRONIX; Part_Preference: Recommended; Component_Country_Of_Origin: Unknown

## Sheet ST_LINK_V3E.SchDoc: ST_LINK_V3E
size A3; Date: Not used; ApprovedBy: Not used; CheckedBy: Not used; Author: Not used; CompanyName: STMicroelectronics; DrawnBy: Not used; Engineer: Not used; Organization: Not used; Address1: Not used; Address2: Not used; Address3: Not used; Address4: Not used; DocumentNumber: Not used; Revision: Not used; SheetNumber: 15; SheetTotal: 16

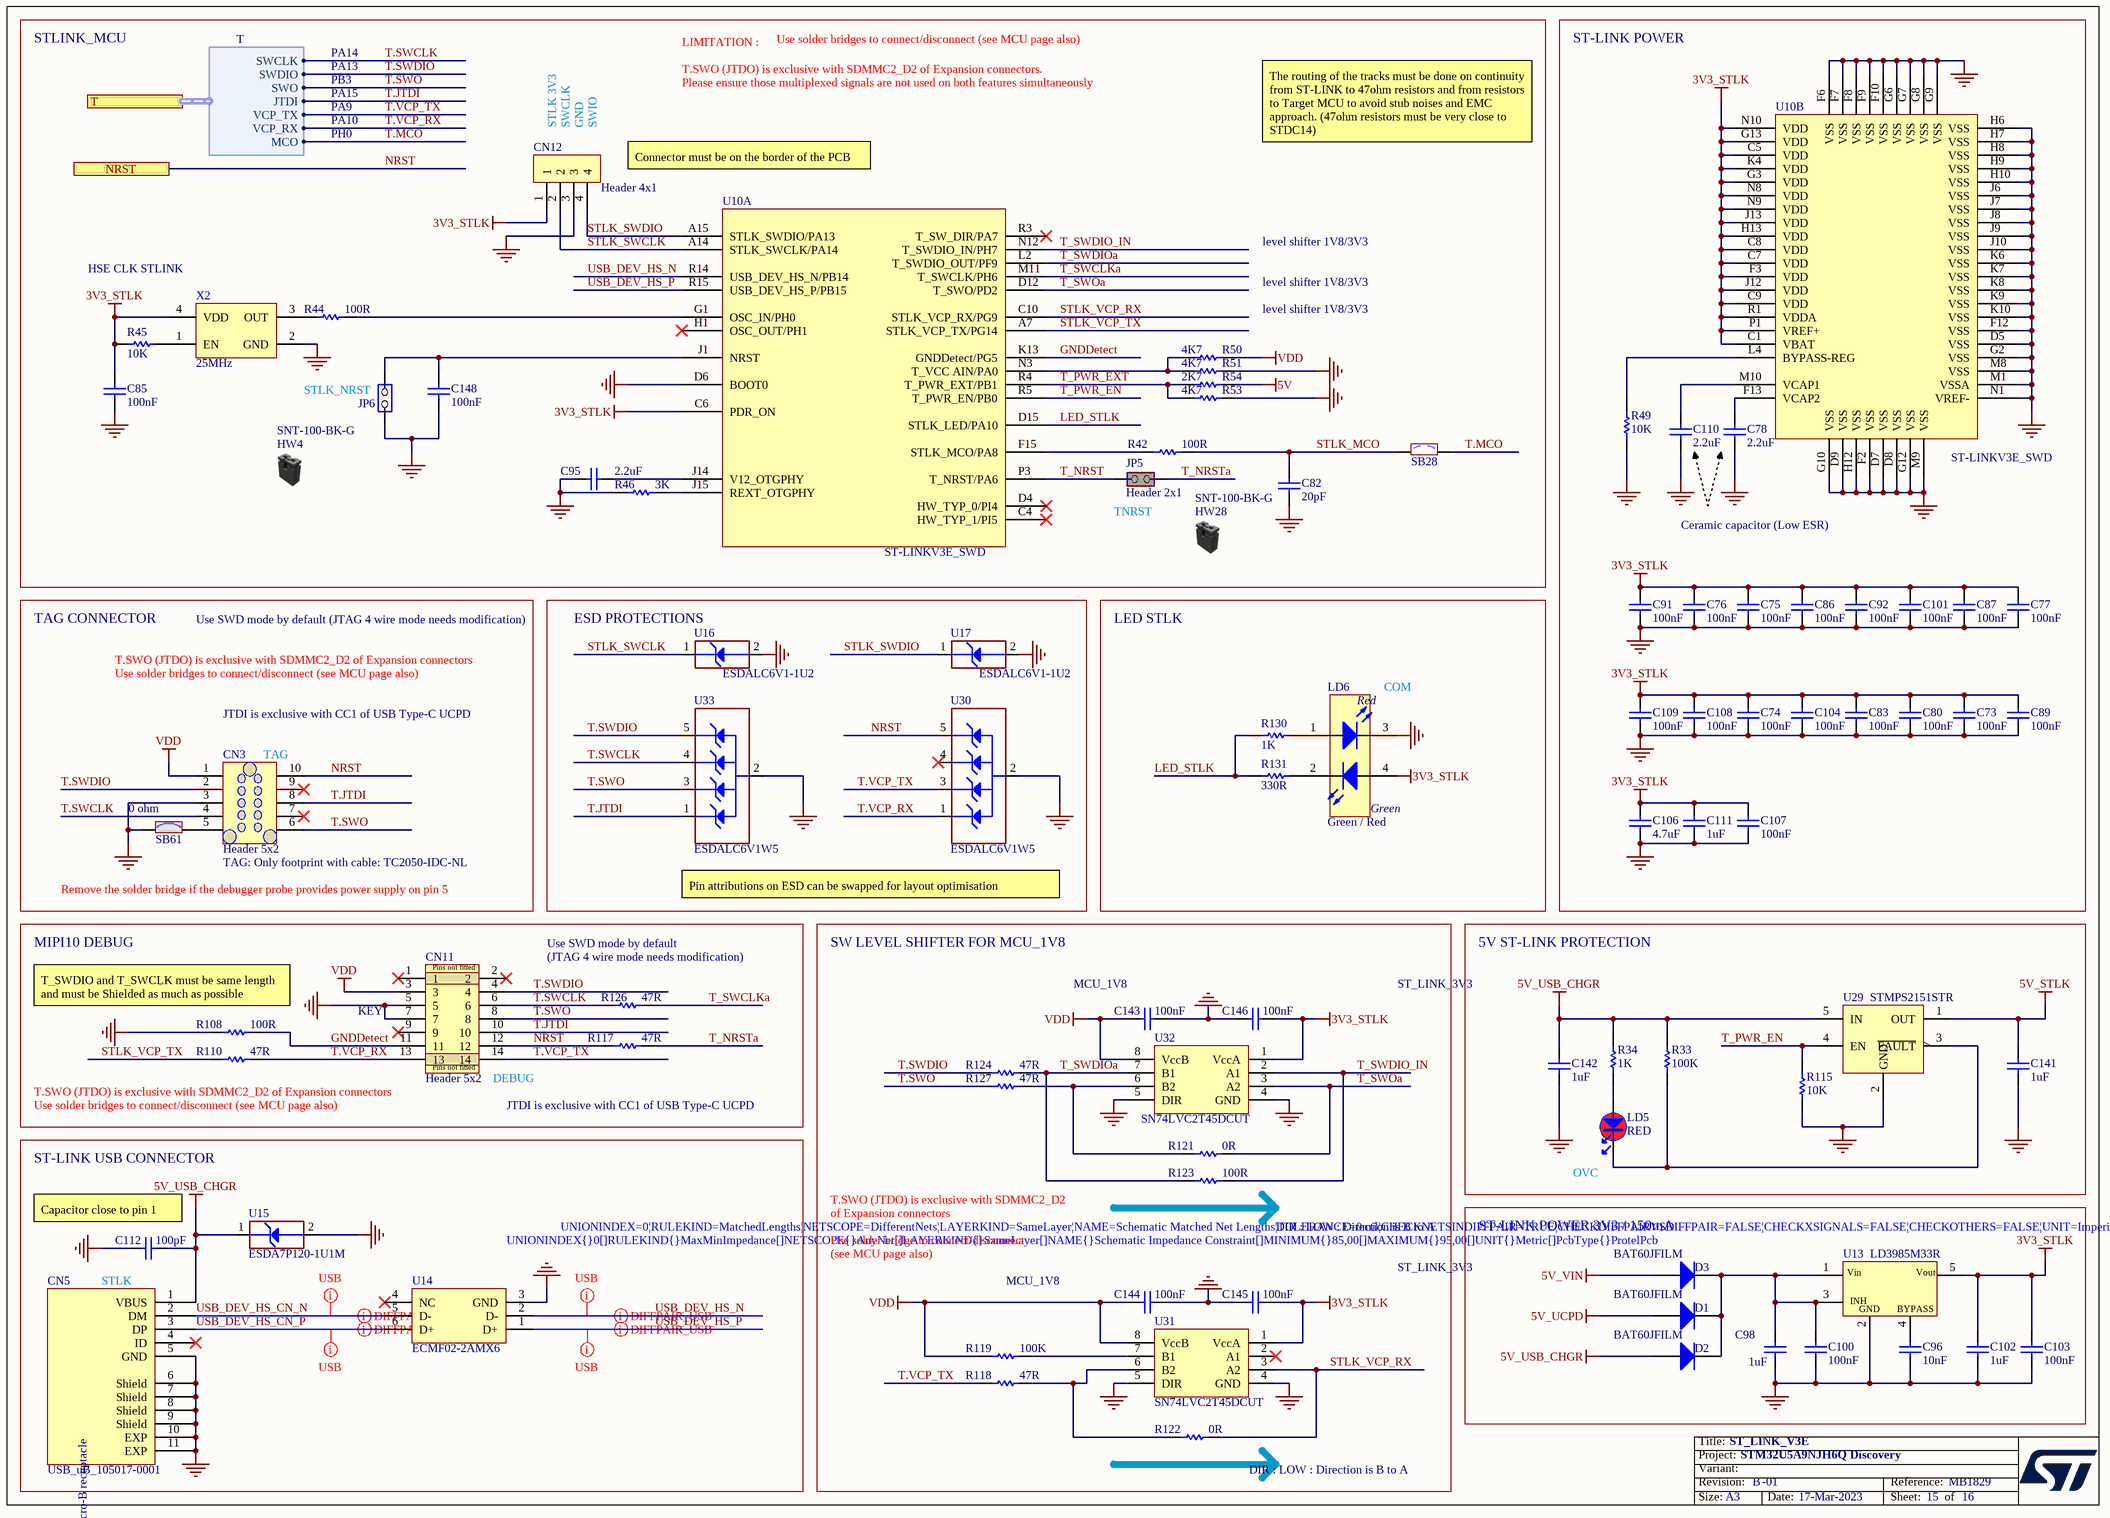
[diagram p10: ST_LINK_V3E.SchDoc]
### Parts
C73  value 100nF  [C0402]  (hidden comment: Capacitor)
C74  value 100nF  [C0402]  (hidden comment: Capacitor)
C75  value 100nF  [C0402]  (hidden comment: Capacitor)
C76  value 100nF  [C0402]  (hidden comment: Capacitor)
C77  value 100nF  [C0402]  (hidden comment: Capacitor)
C78  value 2.2uF  [C0603]  (hidden comment: Capacitor)
C80  value 100nF  [C0402]  (hidden comment: Capacitor)
C82  value 20pF  [C0402]  (hidden comment: Capacitor)
C83  value 100nF  [C0402]  (hidden comment: Capacitor)
C85  value 100nF  [C0402]  (hidden comment: Capacitor)
C86  value 100nF  [C0402]  (hidden comment: Capacitor)
C87  value 100nF  [C0402]  (hidden comment: Capacitor)
C89  value 100nF  [C0402]  (hidden comment: Capacitor)
C91  value 100nF  [C0402]  (hidden comment: Capacitor)
C92  value 100nF  [C0402]  (hidden comment: Capacitor)
C95  value 2.2uF  [C0603]  (hidden comment: Capacitor)
C96  value 10nF  [C0402]  (hidden comment: Capacitor)
C98  value 1uF  [C0402]  (hidden comment: Capacitor)
C100  value 100nF  [C0402]  (hidden comment: Capacitor)
C101  value 100nF  [C0402]  (hidden comment: Capacitor)
C102  value 1uF  [C0402]  (hidden comment: Capacitor)
C103  value 100nF  [C0402]  (hidden comment: Capacitor)
C104  value 100nF  [C0402]  (hidden comment: Capacitor)
C106  value 4.7uF  [C0603]  (hidden comment: Capacitor)
C107  value 100nF  [C0402]  (hidden comment: Capacitor)
C108  value 100nF  [C0402]  (hidden comment: Capacitor)
C109  value 100nF  [C0402]  (hidden comment: Capacitor)
C110  value 2.2uF  [C0603]  (hidden comment: Capacitor)
C111  value 1uF  [C0402]  (hidden comment: Capacitor)
C112  value 100pF  [C0402]  (hidden comment: Capacitor)
C141  value 1uF  [C0402]  (hidden comment: Capacitor)
C142  value 1uF  [C0402]  (hidden comment: Capacitor)
C143  value 100nF  [C0402]  (hidden comment: Capacitor)
C144  value 100nF  [C0402]  (hidden comment: Capacitor)
C145  value 100nF  [C0402]  (hidden comment: Capacitor)
C146  value 100nF  [C0402]  (hidden comment: Capacitor)
C148  value 100nF  [C0402]  (hidden comment: Capacitor)
CN3  value Header 5x2  [CON_TAG-C_TC2050-IDC-NL]  (hidden comment: Tag-10-C)
CN5  value USB_uB_105017-0001  [CON_USBMICROB_MOLEX_105017-0001_H2P90]  (hidden comment: USB_uB_105017.0001)
CN11  value Header 5x2  [CON_STDC14_Receiver_MEDIUM__3D_FTSH-105-01-L-DV-K]  (hidden comment: Header 7x2_MIPI10_on_STDC14)
CN12  Header 4x1  [CON_SAMTEC_TSW-104-07-G-S]
D1  BAT60JFILM  [DIO_SOD323]
D2  BAT60JFILM  [DIO_SOD323]
D3  BAT60JFILM  [DIO_SOD323]
HW4  value SNT-100-BK-G  (hidden comment: Shunt Black 2.54mm)  (mechanical)
HW28  value SNT-100-BK-G  (hidden comment: Shunt Black 2.54mm)  (mechanical)
JP5  value Header 2x1  [CON_SAMTEC_TSW-102-07-G-S]  (hidden comment: Jumper_Header 2x1 Fitted)
JP6  Jumper_Header 2x1  [CON_SAMTEC_TSW-102-07-G-S]  (value not drawn)
LD5  value RED  [LED_0603_OSRAM_LS-Q976-NR-1_RED_1A2K_H0P8]  (hidden comment: LED_red)
LD6  value Green / Red  [LED_BI-GR_WE-150141SV73110]  (hidden comment: LED_BICOLOR)
R33  value 100K  [R0402]  (hidden comment: Resistor)
R34  value 1K  [R0402]  (hidden comment: Resistor)
R42  value 100R  [R0402]  (hidden comment: Resistor)
R44  value 100R  [R0402]  (hidden comment: Resistor)
R45  value 10K  [R0402]  (hidden comment: Resistor)
R46  value 3K  [R0402]  (hidden comment: Resistor)
R49  value 10K  [R0402]  (hidden comment: Resistor)
R50  value 4K7  [R0402]  (hidden comment: Resistor)
R51  value 4K7  [R0402]  (hidden comment: Resistor)
R53  value 4K7  [R0402]  (hidden comment: Resistor)
R54  value 2K7  [R0402]  (hidden comment: Resistor)
R108  value 100R  [R0402]  (hidden comment: Resistor)
R110  value 47R  [R0402]  (hidden comment: Resistor)
R115  value 10K  [R0402]  (hidden comment: Resistor)
R117  value 47R  [R0402]  (hidden comment: Resistor)
R118  value 47R  [R0402]  (hidden comment: Resistor)
R119  value 100K  [R0402]  (hidden comment: Resistor)
R121  value 0R  [R0402]  (hidden comment: Resistor)
R122  value 0R  [R0402]  (hidden comment: Resistor)
R123  value 100R  [R0402]  (hidden comment: Resistor)
R124  value 47R  [R0402]  (hidden comment: Resistor)
R126  value 47R  [R0402]  (hidden comment: Resistor)
R127  value 47R  [R0402]  (hidden comment: Resistor)
R130  value 1K  [R0402]  (hidden comment: Resistor)
R131  value 330R  [R0402]  (hidden comment: Resistor)
SB28  SB_OFF  [SOLDER-BRIDGE_R0402-0R]  (value not drawn)
SB61  value 0 ohm  [SOLDER-BRIDGE_R0402-0R]  (hidden comment: SB_ON)
U10  ST-LINKV3E_SWD  [ICC_UFBGA201_176+25_10X10_P065]  (parts A,B of 2)
U13  LD3985M33R  [REG_SOT23-5L]
U14  ECMF02-2AMX6  [ESD_QFN-6L_1P7X1P5_P050]
U15  value ESDA7P120-1U1M  [ESD_QFN1610_2N_1K_2A]  (hidden comment: ESD-TRANSIL)
U16  value ESDALC6V1-1U2  [ESD_ST0201]  (hidden comment: ESD-TRANSIL)
U17  value ESDALC6V1-1U2  [ESD_ST0201]  (hidden comment: ESD-TRANSIL)
U29  STMPS2151STR  [MOS_SOT23-5L]
U30  ESDALC6V1W5  [ESD_SOT323-5L]
U31  SN74LVC2T45DCUT  [ICC_VSSOP8_DCU_R-PDSO-G8_2X2P30_P050]
U32  SN74LVC2T45DCUT  [ICC_VSSOP8_DCU_R-PDSO-G8_2X2P30_P050]
U33  ESDALC6V1W5  [ESD_SOT323-5L]
X2  value 25MHz  [OSC_NDK_NZ2520SB_4P]  (hidden comment: OSCILLATOR_4_PINS)

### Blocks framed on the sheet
STLINK_MCU: C82 C85 C95 C148 CN12 HW4 HW28 JP5 JP6 R42 R44-R46 R50 R51 R53 R54 SB28 U10 X2
ST-LINK POWER: C73-C78 C80 C83 C86 C87 C89 C91 C92 C101 C104 C106-C111 R49 U10
TAG CONNECTOR: CN3 SB61
ESD PROTECTIONS: U16 U17 U30 U33
LED STLK: LD6 R130 R131
MIPI10 DEBUG: CN11 R108 R110 R117 R126
SW LEVEL SHIFTER FOR MCU_1V8: C143-C146 R118 R119 R121-R124 R127 U31 U32
5V ST-LINK PROTECTION: C141 C142 LD5 R33 R34 R115 U29
ST-LINK USB CONNECTOR: C112 CN5 U14 U15
ST-LINK POWER 3V3 / 150mA: C96 C98 C100 C102 C103 D1-D3 U13

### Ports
NRST, T (harness T)

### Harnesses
T: SWCLK, SWDIO, SWO, JTDI, VCP_RX, VCP_TX, MCO

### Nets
3V3_STLK: C73.1 C74.1 C75.1 C76.1 C77.1 C80.1 C83.1 C85.1 C86.1 C87.1 C89.1 C91.1 C92.1 C101.1 C102.2 C103.2 C104.1 C106.2 C107.1 C108.1 C109.1 C111.2 C145.2 C146.2 CN12.1 LD6.4(Green_anode) R45.1 U10.C1(VBAT) U10.C5(VDD) U10.C6(PDR_ON) U10.C7(VDD) U10.C8(VDD) U10.C9(VDD) U10.F3(VDD) U10.G3(VDD) U10.G13(VDD) U10.H13(VDD) U10.J12(VDD) U10.J13(VDD) U10.K4(VDD) U10.N8(VDD) U10.N9(VDD) U10.N10(VDD) U10.P1(VREF+) U10.R1(VDDA) U13.5(Vout) U31.1(VccA) U32.1(VccA) X2.4(VDD)
5V: R54.1
5V_STLK: C141.2 U29.1(OUT)
5V_UCPD: D1.1(A)
5V_USB_CHGR: C112.2 C142.2 CN5.1(VBUS) D2.1(A) R33.2 R34.2 U15.1(IO1) U29.5(IN)
5V_VIN: D3.1(A)
GND: C73.2 C74.2 C75.2 C76.2 C77.2 C78.1 C80.2 C82.1 C83.2 C85.2 C86.2 C87.2 C89.2 C91.2 C92.2 C95.1 C96.1 C98.1 C100.1 C101.2 C102.1 C103.1 C104.2 C106.1 C107.2 C108.2 C109.2 C110.1 C111.1 C112.1 C141.1 C142.1 C143.2 C144.2 C145.1 C146.1 C148.2 CN3.3 CN5.5(GND) CN5.6(Shield) CN5.7(Shield) CN5.8(Shield) CN5.9(Shield) CN5.10(EXP) CN5.11(EXP) CN11.5 CN11.7 CN12.3 JP6.1(COMMON) LD6.3(RED_cathode) R46.1 R49.1 R51.2 R53.1 R108.1 R115.1 SB61.1 U10.D5(VSS) U10.D6(BOOT0) U10.D7(VSS) U10.D8(VSS) U10.D9(VSS) U10.F2(VSS) U10.F6(VSS) U10.F7(VSS) U10.F8(VSS) U10.F9(VSS) U10.F10(VSS) U10.F12(VSS) U10.G2(VSS) U10.G6(VSS) U10.G7(VSS) U10.G8(VSS) U10.G9(VSS) U10.G10(VSS) U10.G12(VSS) U10.H6(VSS) U10.H7(VSS) U10.H8(VSS) U10.H9(VSS) U10.H10(VSS) U10.H12(VSS) U10.J6(VSS) U10.J7(VSS) U10.J8(VSS) U10.J9(VSS) U10.J10(VSS) U10.K6(VSS) U10.K7(VSS) U10.K8(VSS) U10.K9(VSS) U10.K10(VSS) U10.M1(VSSA) U10.M8(VSS) U10.M9(VSS) U10.N1(VREF-) U13.2(GND) U14.3(GND) U15.2(GND) U16.2(GND) U17.2(GND) U29.2(GND) U30.2(GND) U31.4(GND) U31.5(DIR) U32.4(GND) U32.5(DIR) U33.2(GND) X2.2(GND)
VDD: C143.1 C144.1 CN3.1 CN11.3 R50.2 R119.1 U31.8(VccB) U32.8(VccB)
GNDDetect: CN11.11 R108.2 U10.K13(GNDDetect/PG5)
LED_STLK: R130.2 R131.2 U10.D15(STLK_LED/PA10)
NRST: CN3.10 CN11.12 R117.1 U30.5(IO4) ; port NRST
STLK_MCO: C82.2 R42.2 SB28.1
STLK_SWCLK: CN12.2 U10.A14(STLK_SWCLK/PA14) U16.1(IO1)
STLK_SWDIO: CN12.4 U10.A15(STLK_SWDIO/PA13) U17.1(IO1)
STLK_VCP_RX: R122.2 U10.C10(STLK_VCP_RX/PG9) U31.3(A2)
STLK_VCP_TX: R110.1 U10.A7(STLK_VCP_TX/PG14)
T.JTDI: CN3.8 CN11.10 U33.1(IO1) ; port T.JTDI
T.MCO: SB28.2 ; port T.MCO  [project net PH0-OSC_IN]
T.SWCLK: CN3.4 CN11.6 R126.1 U33.4(IO3) ; port T.SWCLK
T.SWDIO: CN3.2 CN11.4 R124.1 U33.5(IO4) ; port T.SWDIO
T.SWO: CN3.6 CN11.8 R127.1 U33.3(IO2) ; port T.SWO
T.VCP_RX: CN11.13 R110.2 U30.1(IO1) ; port T.VCP_RX
T.VCP_TX: CN11.14 R118.1 U30.3(IO2) ; port T.VCP_TX
T_NRST: JP5.1(COMMON) U10.P3(T_NRST/PA6)
T_NRSTa: JP5.2(NO) R117.2
T_PWR_EN: R115.2 U10.R5(T_PWR_EN/PB0) U29.4(EN)
T_PWR_EXT: R53.2 R54.2 U10.R4(T_PWR_EXT/PB1)
T_SWCLKa: R126.2 U10.M11(T_SWCLK/PH6)
T_SWDIO_IN: R123.2 U10.N12(T_SWDIO_IN/PH7) U32.2(A1)
T_SWDIOa: R123.1 R124.2 U10.L2(T_SWDIO_OUT/PF9) U32.7(B1)
T_SWOa: R121.2 U10.D12(T_SWO/PD2) U32.3(A2)
USB_DEV_HS_CN_N: CN5.2(DM) U14.5(D-)
USB_DEV_HS_CN_P: CN5.3(DP) U14.6(D+)
USB_DEV_HS_N: U10.R14(USB_DEV_HS_N/PB14) U14.2(D-)
USB_DEV_HS_P: U10.R15(USB_DEV_HS_P/PB15) U14.1(D+)
NetC78_2: C78.2 U10.F13(VCAP2)
NetC95_2: C95.2 U10.J14(V12_OTGPHY)
NetC96_2: C96.2 U13.4(BYPASS)
NetC98_2: C98.2 C100.2 D1.2(K) D2.2(K) D3.2(K) U13.1(Vin) U13.3(CE)
NetC110_2: C110.2 U10.M10(VCAP1)
NetC148_1: C148.1 JP6.2(NO) U10.J1(NRST)
NetCN3_5: CN3.5 SB61.2
NetLD5_1: LD5.1 R34.1
NetLD5_2: LD5.2 R33.1 U29.3(~{FAULT})
NetLD6_1: LD6.1(Red_anode) R130.1
NetLD6_2: LD6.2(Green_cathode) R131.1
NetR42_1: R42.1 U10.F15(STLK_MCO/PA8)
NetR44_1: R44.1 X2.3(OUT)
NetR44_2: R44.2 U10.G1(OSC_IN/PH0)
NetR45_2: R45.2 X2.1(EN)
NetR46_2: R46.2 U10.J15(REXT_OTGPHY)
NetR49_2: R49.2 U10.L4(BYPASS-REG)
NetR50_1: R50.1 R51.1 U10.N3(T_VCC_AIN/PA0)
NetR118_2: R118.2 R122.1 U31.6(B2)
NetR119_2: R119.2 U31.7(B1)
NetR121_1: R121.1 R127.2 U32.6(B2)

Not connected (* = marked no-connect by the designer): CN3 7* 9*; CN5 4(ID)*; CN11 1* 2* 9*; U10 C4(HW_TYP_1/PI5)* D4(HW_TYP_0/PI4)* H1(OSC_OUT/PH1)* R3(T_SW_DIR/PA7)*; U14 4(NC)*; U30 4(IO3)*; U31 2(A1)*

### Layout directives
differential pair; rule Impedance Constraint [Min = 85.00    Max = 95.00    ]: USB_DEV_HS_CN_N, USB_DEV_HS_CN_P, USB_DEV_HS_N, USB_DEV_HS_P
rule Undefined; rule Matched Net Lengths [Tolerance = 0mil]; rule Impedance Constraint [Min = 85.00    Max = 95.00    ]: USB_DEV_HS_CN_N, USB_DEV_HS_CN_P, USB_DEV_HS_N, USB_DEV_HS_P

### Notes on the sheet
- Use solder bridges to connect/disconnect (see MCU page also)
- PA14
- PA13
- PB3
- PA15
- PA9
- LIMITATION :
  T.SWO (JTDO) is exclusive with SDMMC2_D2 of Expansion connectors.
  Please ensure those multiplexed signals are not used on both features simultaneously
- PA10
- PH0
- STLK 3V3
- SWCLK
- GND
- SWIO
- Connector must be on the border of the PCB
- The routing of the tracks must be done on continuity from ST-LINK to 47ohm resistors and from resistors to Target MCU to avoid stub noises and EMC approach. (47ohm resistors must be very close to STDC14)
- level shifter 1V8/3V3
- HSE CLK STLINK
- (near JP6) STLK_NRST
- (near JP5) TNRST
- Ceramic capacitor (Low ESR)
- Use SWD mode by default (JTAG 4 wire mode needs modification)
- T.SWO (JTDO) is exclusive with SDMMC2_D2 of Expansion connectors
- JTDI is exclusive with CC1 of USB Type-C UCPD
- (near LD6) COM
- (near CN3) TAG
- Remove the solder bridge if the debugger probe provides power supply on pin 5
- (near CN3) TAG: Only footprint with cable: TC2050-IDC-NL
- Pin attributions on ESD can be swapped for layout optimisation
- Use SWD mode by default
- (near R126) (JTAG 4 wire mode needs modification)
- MCU_1V8
- ST_LINK_3V3
- (near R108) T_SWDIO and T_SWCLK must be same length and must be Shielded as much as possible
- (near CN11) KEY
- (near CN11) DEBUG
- (near LD5) OVC
- (near C112) Capacitor close to pin 1
- T.SWO (JTDO) is exclusive with SDMMC2_D2
- of Expansion connectors
- Use solder bridge to connect/disconnect
- (see MCU page also)
- (near R123) DIR : LOW : Direction is B to A
- STLK
- (near R122) DIR : LOW : Direction is B to A

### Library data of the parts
C73-C77 C80 C83 C85-C87 C89 C91 C92 C100 C101 C103 C104 C107-C109 C143-C146 C148 = MCD-00006: as C36-C40 on sheet MCU_PWR
C78 C95 C110 = MCD-00012: Capacitor, MLCC, 2.2uF, 10V, X5R, +/- 10%, 0603, T=0.8mm; Manufacturer_Part_Number: CC0603KRX5R6BB225; Manufacturer: YAGEO; BMS_Part_Number: 9142010; Part_Preference: Recommended; Component_Country_Of_Origin: China
C82 = MCD-00016: Capacitor, MLCC, 20pF, 50V, NPO, +/- 5%, 0402, T=0.5mm; Manufacturer_Part_Number: CC0402JRNPO9BN200; Manufacturer: YAGEO; Part_Preference: Recommended; Component_Country_Of_Origin: China
C96 = MCD-00011: Capacitor, MLCC, 10nF, 16V, X7R, +/-10%, 0402, T=0.5mm; Manufacturer_Part_Number: CC0402KRX7R7BB103; Manufacturer: YAGEO; Part_Preference: Recommended; Order_Code_RS: 669-8688; Component_Country_Of_Origin: China
C98 C102 C111 C141 C142 = MCD-02609: Capacitor, MLCC, 1uF, 25V, X5R, +/-10%, 0402, T=0.5mm; Part_Preference: Recommended; Manufacturer: YAGEO; Manufacturer_Part_Number: CC0402KRX5R8BB105
C106 = MCD-00009: as C26 on sheet OCTOSPI_FLASH
C112 = MCD-00205: Capacitor, MLCC, 100pF, 50V, NPO, +/-5%, 0402, T=0.5mm; Manufacturer_Part_Number: CC0402JRNPO9BN101; Manufacturer: YAGEO; Part_Preference: Recommended; Component_Country_Of_Origin: China
CN3 = MCD-00031: Header_Plug-of-nails, 5x2, 1.27mm, No legs; Part_Type: Connector; Manufacturer_Part_Number: TC2050-IDC-NL-FP; Manufacturer: TAG-CONNECTLLC; Part_Preference: Recommended
CN5 = MCD-00028: MicroUSB_TypeB, 5pins, 0.65mm, RA, SMD, T=2.9mm; Manufacturer_Part_Number: 1050170001; Manufacturer: MOLEX; Part_Type: Connector; Part_Preference: Recommended; Order_Code_RS: 848-6764; Component_Country_Of_Origin: Unknown
CN11 = MCD-02021: Header_MIPI10, 5x2, 1.27mm, VR, SMD, T=6.1mm; Part_Type: Connector; Manufacturer: SAMTEC; Manufacturer_Part_Number: FTSH-105-01-L-DV-K-P-TR; Part_Preference: Recommended; Component_Country_Of_Origin: China, Costa Rica, Malaysia, United States, Vietnam
CN12 = MCD-00029: Header, 4x1, 2.54mm, VR, TH, T=5.84mm/2.54mm; Manufacturer_Part_Number: TSW-104-07-G-S; Manufacturer: SAMTEC; Part_Type: Connector; Part_Preference: Recommended; Order_Code_RS: 161-2261; Component_Country_Of_Origin: China, Costa Rica, Malaysia, United States, Vietnam
D1-D3 = MCD-00034: Manufacturer: STMICROELECTRONICS; Part_Type: Diode; BMS_Part_Number: 9151097; Part_Preference: Recommended; Manufacturer_HQ_COO: EU; Component_Country_Of_Origin: China
HW4 HW28 = MCD-00043: SHUNT 2.54mm BLACK; Manufacturer: SAMTEC; Part_Type: Misc; Part_Preference: Recommended; Component_Country_Of_Origin: China, Costa Rica, Malaysia, United States, Vietnam
JP5 = MCD-01904: Header, 2x1, 2.54mm, VR, TH, T=5.84mm/2.54mm; Part_Preference: Recommended; Part_Type: Connector; Manufacturer: SAMTEC; Manufacturer_Part_Number: TSW-102-07-G-S; Order_Code_RS: 155-7981; Component_Country_Of_Origin: China, Costa Rica, Malaysia, United States, Vietnam
JP6 = MCD-00045: Header, 2x1, 2.54mm, VR, TH, T=5.84mm/2.54mm; Part_Type: Connector; Manufacturer_Part_Number: TSW-102-07-G-S; Manufacturer: SAMTEC; Part_Preference: Recommended; Order_Code_RS: 155-5312; Component_Country_Of_Origin: China, Costa Rica, Malaysia, United States, Vietnam
LD5 = MCD-00586: LED Red, 0603 SMD, Forward Voltage Typ=2V, Max=2.5V; Manufacturer_Part_Number: LS Q976-NR-1; Manufacturer: OSRAM OPTO SEMICONDUCTORS; Part_Type: Display; Part_Preference: Recommended; Component_Country_Of_Origin: Unknown; ShowFields: YES; ID: 3158
LD6 = MCD-02631: LED Bicolor, Green/Red, 2V, 20mA,  4-PLCC; Part_Type: Display; Part_Preference: Recommended; Manufacturer: WURTH ELEKTRONIK; Manufacturer_Part_Number: 150141SV73110; Order_Code_RS: 184-6963; Component_Country_Of_Origin: China; ShowFields: YES; ID: 4737
R33 R119 = MCD-00059: Resistor, 100K, 0402, +/-1%, 1/16W; Manufacturer_Part_Number: RC0402FR-07100KL; Manufacturer: YAGEO; Part_Preference: Recommended; Component_Country_Of_Origin: China
R34 R130 = MCD-00061: Resistor, 1K, 0402, +/-1%,1/16W; Manufacturer_Part_Number: RC0402FR-071KL; Manufacturer: YAGEO; Part_Preference: Recommended; Component_Country_Of_Origin: China; ShowFields: YES; ID: 2532
R42 R44 R108 R123 = MCD-00067: Resistor, 100R, 0402, +/- 1%, 1/16W; Manufacturer_Part_Number: RC0402FR-07100RL; Manufacturer: YAGEO; Part_Preference: Recommended; Component_Country_Of_Origin: China
R45 R49 R115 = MCD-00053: as R20 on sheet OCTOSPI_FLASH
R46 = MCD-00185: Resistor, 3K, 0402, +/-1%, 1/16W; Manufacturer_Part_Number: RC0402FR-073KL; Manufacturer: YAGEO; Part_Preference: Recommended; Component_Country_Of_Origin: China
R50 R51 R53 = MCD-00065: Resistor, 4K7, 0402, +/-1%, 1/16W; Manufacturer_Part_Number: RC0402FR-074K7L; Manufacturer: YAGEO; Part_Preference: Recommended; Component_Country_Of_Origin: China
R54 = MCD-00055: Resistor, 2K7, 0402, +/-1%, 1/16W; Manufacturer_Part_Number: RC0402FR-072K7L; Manufacturer: YAGEO; Part_Preference: Recommended; Component_Country_Of_Origin: China
R110 R117 R118 R124 R126 R127 = MCD-00481: Resistor, 47R, 0402, +/-1%, 1/16W; Manufacturer_Part_Number: RC0402FR-0747RL; Manufacturer: YAGEO; Part_Preference: Recommended; Component_Country_Of_Origin: China
R121 R122 = MCD-00052: as R22-R24 on sheet OCTOSPI_FLASH
R131 = MCD-00062: Resistor, 330R, 0402, +/-1%, 1/16W; Manufacturer_Part_Number: RC0402FR-07330RL; Manufacturer: YAGEO; Part_Preference: Recommended; Component_Country_Of_Origin: China
SB28 = MCD-02162: as SB34 on sheet MCU_IO
SB61 = MCD-01618: Solder Bridge 0402 ON; Part_Type: Misc; Part_Preference: Recommended; Manufacturer: YAGEO; Manufacturer_Part_Number: RC0402JR-070RL; Order_Code_RS: 618-5804; Component_Country_Of_Origin: China; ShowFields: YES; ID: 3718
U10 = MCD-00596: STM32F723IEK  (STM32F7) BGA176; Part_Type: IC; Manufacturer_Part_Number: STM32F723IEK6; Manufacturer: STMICROELECTRONICS; BMS_Part_Number: 9175300; Part_Preference: Recommended; Manufacturer_HQ_COO: EU; Component_Country_Of_Origin: Philippines
U13 = MCD-00086: Ultra low drop-low noise BiCMOS voltage, regulators low ESR capacitors compatible; Manufacturer: STMICROELECTRONICS; Part_Type: IC; BMS_Part_Number: 9176161; Part_Preference: Recommended; Manufacturer_HQ_COO: EU; Component_Country_Of_Origin: China
U14 = MCD-00649: Common mode filter with ESD protection for USB 2.0 interface; Part_Type: Diode; Manufacturer: STMICROELECTRONICS; BMS_Part_Number: 9151138; Part_Preference: Recommended; Manufacturer_HQ_COO: EU; Component_Country_Of_Origin: China
U15 = MCD-01026: High power transient voltage suppressor; Part_Type: Diode; Manufacturer: STMICROELECTRONICS; BMS_Part_Number: 9179046; Part_Preference: Recommended; Manufacturer_HQ_COO: EU; Component_Country_Of_Origin: China
U16 U17 = MCD-00170: ESD protection 6V1; Part_Type: Diode; Manufacturer: STMICROELECTRONICS; BMS_Part_Number: 9151132; Part_Preference: Recommended; Manufacturer_HQ_COO: EU; Component_Country_Of_Origin: China
U29 = MCD-00159: 500mA, Enhanced single channel power switches with active high enable pin; Part_Type: IC; Manufacturer: STMICROELECTRONICS; BMS_Part_Number: 9159009; Part_Preference: Recommended; Manufacturer_HQ_COO: EU; Component_Country_Of_Origin: Malaysia
U30 U33 = MCD-00136: Dual Transil array for ESD protection; Part_Type: Diode; Manufacturer: STMICROELECTRONICS; BMS_Part_Number: 9151112; Part_Preference: Recommended; Manufacturer_HQ_COO: EU; Component_Country_Of_Origin: China
U31 U32 = MCD-00264: Dual bit dual supply bus transceiver; Part_Type: IC; Manufacturer: TEXAS INSTRUMENTS; BMS_Part_Number: 9169311; Part_Preference: Recommended; Component_Country_Of_Origin: Thailand
X2 = MCD-00597: Oscillator, SPXO, 25Mhz, +/-50ppm, 3V3, square wave, 2.5x2mm; Part_Type: Crystal_Osc; Manufacturer_Part_Number: NZ2520SH-25MHZ-END4869C; Manufacturer: NDK; BMS_Part_Number: 9157050; Part_Preference: Recommended; Component_Country_Of_Origin: Unknown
